VERSION 5.7 ;
BUSBITCHARS "[]" ;
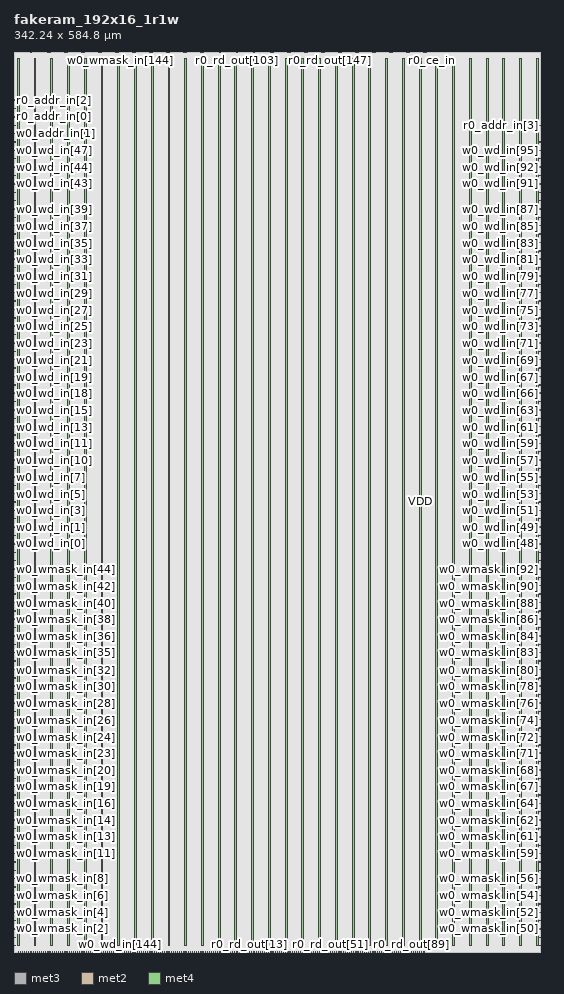
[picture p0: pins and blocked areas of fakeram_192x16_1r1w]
MACRO fakeram_192x16_1r1w
  FOREIGN fakeram_192x16_1r1w 0 0 ;
  SYMMETRY X Y R90 ;
  SIZE 342.240 BY 584.800 ;
  CLASS BLOCK ;
  PIN w0_wmask_in[0]
    DIRECTION INPUT ;
    USE SIGNAL ;
    SHAPE ABUTMENT ;
    PORT
      LAYER met3 ;
      RECT 0.000 3.930 0.900 4.230 ;
    END
  END w0_wmask_in[0]
  PIN w0_wmask_in[1]
    DIRECTION INPUT ;
    USE SIGNAL ;
    SHAPE ABUTMENT ;
    PORT
      LAYER met3 ;
      RECT 0.000 9.370 0.900 9.670 ;
    END
  END w0_wmask_in[1]
  PIN w0_wmask_in[2]
    DIRECTION INPUT ;
    USE SIGNAL ;
    SHAPE ABUTMENT ;
    PORT
      LAYER met3 ;
      RECT 0.000 14.810 0.900 15.110 ;
    END
  END w0_wmask_in[2]
  PIN w0_wmask_in[3]
    DIRECTION INPUT ;
    USE SIGNAL ;
    SHAPE ABUTMENT ;
    PORT
      LAYER met3 ;
      RECT 0.000 20.250 0.900 20.550 ;
    END
  END w0_wmask_in[3]
  PIN w0_wmask_in[4]
    DIRECTION INPUT ;
    USE SIGNAL ;
    SHAPE ABUTMENT ;
    PORT
      LAYER met3 ;
      RECT 0.000 25.690 0.900 25.990 ;
    END
  END w0_wmask_in[4]
  PIN w0_wmask_in[5]
    DIRECTION INPUT ;
    USE SIGNAL ;
    SHAPE ABUTMENT ;
    PORT
      LAYER met3 ;
      RECT 0.000 31.130 0.900 31.430 ;
    END
  END w0_wmask_in[5]
  PIN w0_wmask_in[6]
    DIRECTION INPUT ;
    USE SIGNAL ;
    SHAPE ABUTMENT ;
    PORT
      LAYER met3 ;
      RECT 0.000 36.570 0.900 36.870 ;
    END
  END w0_wmask_in[6]
  PIN w0_wmask_in[7]
    DIRECTION INPUT ;
    USE SIGNAL ;
    SHAPE ABUTMENT ;
    PORT
      LAYER met3 ;
      RECT 0.000 42.010 0.900 42.310 ;
    END
  END w0_wmask_in[7]
  PIN w0_wmask_in[8]
    DIRECTION INPUT ;
    USE SIGNAL ;
    SHAPE ABUTMENT ;
    PORT
      LAYER met3 ;
      RECT 0.000 47.450 0.900 47.750 ;
    END
  END w0_wmask_in[8]
  PIN w0_wmask_in[9]
    DIRECTION INPUT ;
    USE SIGNAL ;
    SHAPE ABUTMENT ;
    PORT
      LAYER met3 ;
      RECT 0.000 52.890 0.900 53.190 ;
    END
  END w0_wmask_in[9]
  PIN w0_wmask_in[10]
    DIRECTION INPUT ;
    USE SIGNAL ;
    SHAPE ABUTMENT ;
    PORT
      LAYER met3 ;
      RECT 0.000 58.330 0.900 58.630 ;
    END
  END w0_wmask_in[10]
  PIN w0_wmask_in[11]
    DIRECTION INPUT ;
    USE SIGNAL ;
    SHAPE ABUTMENT ;
    PORT
      LAYER met3 ;
      RECT 0.000 63.770 0.900 64.070 ;
    END
  END w0_wmask_in[11]
  PIN w0_wmask_in[12]
    DIRECTION INPUT ;
    USE SIGNAL ;
    SHAPE ABUTMENT ;
    PORT
      LAYER met3 ;
      RECT 0.000 69.210 0.900 69.510 ;
    END
  END w0_wmask_in[12]
  PIN w0_wmask_in[13]
    DIRECTION INPUT ;
    USE SIGNAL ;
    SHAPE ABUTMENT ;
    PORT
      LAYER met3 ;
      RECT 0.000 74.650 0.900 74.950 ;
    END
  END w0_wmask_in[13]
  PIN w0_wmask_in[14]
    DIRECTION INPUT ;
    USE SIGNAL ;
    SHAPE ABUTMENT ;
    PORT
      LAYER met3 ;
      RECT 0.000 80.090 0.900 80.390 ;
    END
  END w0_wmask_in[14]
  PIN w0_wmask_in[15]
    DIRECTION INPUT ;
    USE SIGNAL ;
    SHAPE ABUTMENT ;
    PORT
      LAYER met3 ;
      RECT 0.000 85.530 0.900 85.830 ;
    END
  END w0_wmask_in[15]
  PIN w0_wmask_in[16]
    DIRECTION INPUT ;
    USE SIGNAL ;
    SHAPE ABUTMENT ;
    PORT
      LAYER met3 ;
      RECT 0.000 90.970 0.900 91.270 ;
    END
  END w0_wmask_in[16]
  PIN w0_wmask_in[17]
    DIRECTION INPUT ;
    USE SIGNAL ;
    SHAPE ABUTMENT ;
    PORT
      LAYER met3 ;
      RECT 0.000 96.410 0.900 96.710 ;
    END
  END w0_wmask_in[17]
  PIN w0_wmask_in[18]
    DIRECTION INPUT ;
    USE SIGNAL ;
    SHAPE ABUTMENT ;
    PORT
      LAYER met3 ;
      RECT 0.000 101.850 0.900 102.150 ;
    END
  END w0_wmask_in[18]
  PIN w0_wmask_in[19]
    DIRECTION INPUT ;
    USE SIGNAL ;
    SHAPE ABUTMENT ;
    PORT
      LAYER met3 ;
      RECT 0.000 107.290 0.900 107.590 ;
    END
  END w0_wmask_in[19]
  PIN w0_wmask_in[20]
    DIRECTION INPUT ;
    USE SIGNAL ;
    SHAPE ABUTMENT ;
    PORT
      LAYER met3 ;
      RECT 0.000 112.730 0.900 113.030 ;
    END
  END w0_wmask_in[20]
  PIN w0_wmask_in[21]
    DIRECTION INPUT ;
    USE SIGNAL ;
    SHAPE ABUTMENT ;
    PORT
      LAYER met3 ;
      RECT 0.000 118.170 0.900 118.470 ;
    END
  END w0_wmask_in[21]
  PIN w0_wmask_in[22]
    DIRECTION INPUT ;
    USE SIGNAL ;
    SHAPE ABUTMENT ;
    PORT
      LAYER met3 ;
      RECT 0.000 123.610 0.900 123.910 ;
    END
  END w0_wmask_in[22]
  PIN w0_wmask_in[23]
    DIRECTION INPUT ;
    USE SIGNAL ;
    SHAPE ABUTMENT ;
    PORT
      LAYER met3 ;
      RECT 0.000 129.050 0.900 129.350 ;
    END
  END w0_wmask_in[23]
  PIN w0_wmask_in[24]
    DIRECTION INPUT ;
    USE SIGNAL ;
    SHAPE ABUTMENT ;
    PORT
      LAYER met3 ;
      RECT 0.000 134.490 0.900 134.790 ;
    END
  END w0_wmask_in[24]
  PIN w0_wmask_in[25]
    DIRECTION INPUT ;
    USE SIGNAL ;
    SHAPE ABUTMENT ;
    PORT
      LAYER met3 ;
      RECT 0.000 139.930 0.900 140.230 ;
    END
  END w0_wmask_in[25]
  PIN w0_wmask_in[26]
    DIRECTION INPUT ;
    USE SIGNAL ;
    SHAPE ABUTMENT ;
    PORT
      LAYER met3 ;
      RECT 0.000 145.370 0.900 145.670 ;
    END
  END w0_wmask_in[26]
  PIN w0_wmask_in[27]
    DIRECTION INPUT ;
    USE SIGNAL ;
    SHAPE ABUTMENT ;
    PORT
      LAYER met3 ;
      RECT 0.000 150.810 0.900 151.110 ;
    END
  END w0_wmask_in[27]
  PIN w0_wmask_in[28]
    DIRECTION INPUT ;
    USE SIGNAL ;
    SHAPE ABUTMENT ;
    PORT
      LAYER met3 ;
      RECT 0.000 156.250 0.900 156.550 ;
    END
  END w0_wmask_in[28]
  PIN w0_wmask_in[29]
    DIRECTION INPUT ;
    USE SIGNAL ;
    SHAPE ABUTMENT ;
    PORT
      LAYER met3 ;
      RECT 0.000 161.690 0.900 161.990 ;
    END
  END w0_wmask_in[29]
  PIN w0_wmask_in[30]
    DIRECTION INPUT ;
    USE SIGNAL ;
    SHAPE ABUTMENT ;
    PORT
      LAYER met3 ;
      RECT 0.000 167.130 0.900 167.430 ;
    END
  END w0_wmask_in[30]
  PIN w0_wmask_in[31]
    DIRECTION INPUT ;
    USE SIGNAL ;
    SHAPE ABUTMENT ;
    PORT
      LAYER met3 ;
      RECT 0.000 172.570 0.900 172.870 ;
    END
  END w0_wmask_in[31]
  PIN w0_wmask_in[32]
    DIRECTION INPUT ;
    USE SIGNAL ;
    SHAPE ABUTMENT ;
    PORT
      LAYER met3 ;
      RECT 0.000 178.010 0.900 178.310 ;
    END
  END w0_wmask_in[32]
  PIN w0_wmask_in[33]
    DIRECTION INPUT ;
    USE SIGNAL ;
    SHAPE ABUTMENT ;
    PORT
      LAYER met3 ;
      RECT 0.000 183.450 0.900 183.750 ;
    END
  END w0_wmask_in[33]
  PIN w0_wmask_in[34]
    DIRECTION INPUT ;
    USE SIGNAL ;
    SHAPE ABUTMENT ;
    PORT
      LAYER met3 ;
      RECT 0.000 188.890 0.900 189.190 ;
    END
  END w0_wmask_in[34]
  PIN w0_wmask_in[35]
    DIRECTION INPUT ;
    USE SIGNAL ;
    SHAPE ABUTMENT ;
    PORT
      LAYER met3 ;
      RECT 0.000 194.330 0.900 194.630 ;
    END
  END w0_wmask_in[35]
  PIN w0_wmask_in[36]
    DIRECTION INPUT ;
    USE SIGNAL ;
    SHAPE ABUTMENT ;
    PORT
      LAYER met3 ;
      RECT 0.000 199.770 0.900 200.070 ;
    END
  END w0_wmask_in[36]
  PIN w0_wmask_in[37]
    DIRECTION INPUT ;
    USE SIGNAL ;
    SHAPE ABUTMENT ;
    PORT
      LAYER met3 ;
      RECT 0.000 205.210 0.900 205.510 ;
    END
  END w0_wmask_in[37]
  PIN w0_wmask_in[38]
    DIRECTION INPUT ;
    USE SIGNAL ;
    SHAPE ABUTMENT ;
    PORT
      LAYER met3 ;
      RECT 0.000 210.650 0.900 210.950 ;
    END
  END w0_wmask_in[38]
  PIN w0_wmask_in[39]
    DIRECTION INPUT ;
    USE SIGNAL ;
    SHAPE ABUTMENT ;
    PORT
      LAYER met3 ;
      RECT 0.000 216.090 0.900 216.390 ;
    END
  END w0_wmask_in[39]
  PIN w0_wmask_in[40]
    DIRECTION INPUT ;
    USE SIGNAL ;
    SHAPE ABUTMENT ;
    PORT
      LAYER met3 ;
      RECT 0.000 221.530 0.900 221.830 ;
    END
  END w0_wmask_in[40]
  PIN w0_wmask_in[41]
    DIRECTION INPUT ;
    USE SIGNAL ;
    SHAPE ABUTMENT ;
    PORT
      LAYER met3 ;
      RECT 0.000 226.970 0.900 227.270 ;
    END
  END w0_wmask_in[41]
  PIN w0_wmask_in[42]
    DIRECTION INPUT ;
    USE SIGNAL ;
    SHAPE ABUTMENT ;
    PORT
      LAYER met3 ;
      RECT 0.000 232.410 0.900 232.710 ;
    END
  END w0_wmask_in[42]
  PIN w0_wmask_in[43]
    DIRECTION INPUT ;
    USE SIGNAL ;
    SHAPE ABUTMENT ;
    PORT
      LAYER met3 ;
      RECT 0.000 237.850 0.900 238.150 ;
    END
  END w0_wmask_in[43]
  PIN w0_wmask_in[44]
    DIRECTION INPUT ;
    USE SIGNAL ;
    SHAPE ABUTMENT ;
    PORT
      LAYER met3 ;
      RECT 0.000 243.290 0.900 243.590 ;
    END
  END w0_wmask_in[44]
  PIN w0_wmask_in[45]
    DIRECTION INPUT ;
    USE SIGNAL ;
    SHAPE ABUTMENT ;
    PORT
      LAYER met3 ;
      RECT 0.000 248.730 0.900 249.030 ;
    END
  END w0_wmask_in[45]
  PIN w0_wmask_in[46]
    DIRECTION INPUT ;
    USE SIGNAL ;
    SHAPE ABUTMENT ;
    PORT
      LAYER met3 ;
      RECT 0.000 254.170 0.900 254.470 ;
    END
  END w0_wmask_in[46]
  PIN w0_wmask_in[47]
    DIRECTION INPUT ;
    USE SIGNAL ;
    SHAPE ABUTMENT ;
    PORT
      LAYER met3 ;
      RECT 0.000 259.610 0.900 259.910 ;
    END
  END w0_wmask_in[47]
  PIN w0_wmask_in[48]
    DIRECTION INPUT ;
    USE SIGNAL ;
    SHAPE ABUTMENT ;
    PORT
      LAYER met3 ;
      RECT 341.340 3.930 342.240 4.230 ;
    END
  END w0_wmask_in[48]
  PIN w0_wmask_in[49]
    DIRECTION INPUT ;
    USE SIGNAL ;
    SHAPE ABUTMENT ;
    PORT
      LAYER met3 ;
      RECT 341.340 9.370 342.240 9.670 ;
    END
  END w0_wmask_in[49]
  PIN w0_wmask_in[50]
    DIRECTION INPUT ;
    USE SIGNAL ;
    SHAPE ABUTMENT ;
    PORT
      LAYER met3 ;
      RECT 341.340 14.810 342.240 15.110 ;
    END
  END w0_wmask_in[50]
  PIN w0_wmask_in[51]
    DIRECTION INPUT ;
    USE SIGNAL ;
    SHAPE ABUTMENT ;
    PORT
      LAYER met3 ;
      RECT 341.340 20.250 342.240 20.550 ;
    END
  END w0_wmask_in[51]
  PIN w0_wmask_in[52]
    DIRECTION INPUT ;
    USE SIGNAL ;
    SHAPE ABUTMENT ;
    PORT
      LAYER met3 ;
      RECT 341.340 25.690 342.240 25.990 ;
    END
  END w0_wmask_in[52]
  PIN w0_wmask_in[53]
    DIRECTION INPUT ;
    USE SIGNAL ;
    SHAPE ABUTMENT ;
    PORT
      LAYER met3 ;
      RECT 341.340 31.130 342.240 31.430 ;
    END
  END w0_wmask_in[53]
  PIN w0_wmask_in[54]
    DIRECTION INPUT ;
    USE SIGNAL ;
    SHAPE ABUTMENT ;
    PORT
      LAYER met3 ;
      RECT 341.340 36.570 342.240 36.870 ;
    END
  END w0_wmask_in[54]
  PIN w0_wmask_in[55]
    DIRECTION INPUT ;
    USE SIGNAL ;
    SHAPE ABUTMENT ;
    PORT
      LAYER met3 ;
      RECT 341.340 42.010 342.240 42.310 ;
    END
  END w0_wmask_in[55]
  PIN w0_wmask_in[56]
    DIRECTION INPUT ;
    USE SIGNAL ;
    SHAPE ABUTMENT ;
    PORT
      LAYER met3 ;
      RECT 341.340 47.450 342.240 47.750 ;
    END
  END w0_wmask_in[56]
  PIN w0_wmask_in[57]
    DIRECTION INPUT ;
    USE SIGNAL ;
    SHAPE ABUTMENT ;
    PORT
      LAYER met3 ;
      RECT 341.340 52.890 342.240 53.190 ;
    END
  END w0_wmask_in[57]
  PIN w0_wmask_in[58]
    DIRECTION INPUT ;
    USE SIGNAL ;
    SHAPE ABUTMENT ;
    PORT
      LAYER met3 ;
      RECT 341.340 58.330 342.240 58.630 ;
    END
  END w0_wmask_in[58]
  PIN w0_wmask_in[59]
    DIRECTION INPUT ;
    USE SIGNAL ;
    SHAPE ABUTMENT ;
    PORT
      LAYER met3 ;
      RECT 341.340 63.770 342.240 64.070 ;
    END
  END w0_wmask_in[59]
  PIN w0_wmask_in[60]
    DIRECTION INPUT ;
    USE SIGNAL ;
    SHAPE ABUTMENT ;
    PORT
      LAYER met3 ;
      RECT 341.340 69.210 342.240 69.510 ;
    END
  END w0_wmask_in[60]
  PIN w0_wmask_in[61]
    DIRECTION INPUT ;
    USE SIGNAL ;
    SHAPE ABUTMENT ;
    PORT
      LAYER met3 ;
      RECT 341.340 74.650 342.240 74.950 ;
    END
  END w0_wmask_in[61]
  PIN w0_wmask_in[62]
    DIRECTION INPUT ;
    USE SIGNAL ;
    SHAPE ABUTMENT ;
    PORT
      LAYER met3 ;
      RECT 341.340 80.090 342.240 80.390 ;
    END
  END w0_wmask_in[62]
  PIN w0_wmask_in[63]
    DIRECTION INPUT ;
    USE SIGNAL ;
    SHAPE ABUTMENT ;
    PORT
      LAYER met3 ;
      RECT 341.340 85.530 342.240 85.830 ;
    END
  END w0_wmask_in[63]
  PIN w0_wmask_in[64]
    DIRECTION INPUT ;
    USE SIGNAL ;
    SHAPE ABUTMENT ;
    PORT
      LAYER met3 ;
      RECT 341.340 90.970 342.240 91.270 ;
    END
  END w0_wmask_in[64]
  PIN w0_wmask_in[65]
    DIRECTION INPUT ;
    USE SIGNAL ;
    SHAPE ABUTMENT ;
    PORT
      LAYER met3 ;
      RECT 341.340 96.410 342.240 96.710 ;
    END
  END w0_wmask_in[65]
  PIN w0_wmask_in[66]
    DIRECTION INPUT ;
    USE SIGNAL ;
    SHAPE ABUTMENT ;
    PORT
      LAYER met3 ;
      RECT 341.340 101.850 342.240 102.150 ;
    END
  END w0_wmask_in[66]
  PIN w0_wmask_in[67]
    DIRECTION INPUT ;
    USE SIGNAL ;
    SHAPE ABUTMENT ;
    PORT
      LAYER met3 ;
      RECT 341.340 107.290 342.240 107.590 ;
    END
  END w0_wmask_in[67]
  PIN w0_wmask_in[68]
    DIRECTION INPUT ;
    USE SIGNAL ;
    SHAPE ABUTMENT ;
    PORT
      LAYER met3 ;
      RECT 341.340 112.730 342.240 113.030 ;
    END
  END w0_wmask_in[68]
  PIN w0_wmask_in[69]
    DIRECTION INPUT ;
    USE SIGNAL ;
    SHAPE ABUTMENT ;
    PORT
      LAYER met3 ;
      RECT 341.340 118.170 342.240 118.470 ;
    END
  END w0_wmask_in[69]
  PIN w0_wmask_in[70]
    DIRECTION INPUT ;
    USE SIGNAL ;
    SHAPE ABUTMENT ;
    PORT
      LAYER met3 ;
      RECT 341.340 123.610 342.240 123.910 ;
    END
  END w0_wmask_in[70]
  PIN w0_wmask_in[71]
    DIRECTION INPUT ;
    USE SIGNAL ;
    SHAPE ABUTMENT ;
    PORT
      LAYER met3 ;
      RECT 341.340 129.050 342.240 129.350 ;
    END
  END w0_wmask_in[71]
  PIN w0_wmask_in[72]
    DIRECTION INPUT ;
    USE SIGNAL ;
    SHAPE ABUTMENT ;
    PORT
      LAYER met3 ;
      RECT 341.340 134.490 342.240 134.790 ;
    END
  END w0_wmask_in[72]
  PIN w0_wmask_in[73]
    DIRECTION INPUT ;
    USE SIGNAL ;
    SHAPE ABUTMENT ;
    PORT
      LAYER met3 ;
      RECT 341.340 139.930 342.240 140.230 ;
    END
  END w0_wmask_in[73]
  PIN w0_wmask_in[74]
    DIRECTION INPUT ;
    USE SIGNAL ;
    SHAPE ABUTMENT ;
    PORT
      LAYER met3 ;
      RECT 341.340 145.370 342.240 145.670 ;
    END
  END w0_wmask_in[74]
  PIN w0_wmask_in[75]
    DIRECTION INPUT ;
    USE SIGNAL ;
    SHAPE ABUTMENT ;
    PORT
      LAYER met3 ;
      RECT 341.340 150.810 342.240 151.110 ;
    END
  END w0_wmask_in[75]
  PIN w0_wmask_in[76]
    DIRECTION INPUT ;
    USE SIGNAL ;
    SHAPE ABUTMENT ;
    PORT
      LAYER met3 ;
      RECT 341.340 156.250 342.240 156.550 ;
    END
  END w0_wmask_in[76]
  PIN w0_wmask_in[77]
    DIRECTION INPUT ;
    USE SIGNAL ;
    SHAPE ABUTMENT ;
    PORT
      LAYER met3 ;
      RECT 341.340 161.690 342.240 161.990 ;
    END
  END w0_wmask_in[77]
  PIN w0_wmask_in[78]
    DIRECTION INPUT ;
    USE SIGNAL ;
    SHAPE ABUTMENT ;
    PORT
      LAYER met3 ;
      RECT 341.340 167.130 342.240 167.430 ;
    END
  END w0_wmask_in[78]
  PIN w0_wmask_in[79]
    DIRECTION INPUT ;
    USE SIGNAL ;
    SHAPE ABUTMENT ;
    PORT
      LAYER met3 ;
      RECT 341.340 172.570 342.240 172.870 ;
    END
  END w0_wmask_in[79]
  PIN w0_wmask_in[80]
    DIRECTION INPUT ;
    USE SIGNAL ;
    SHAPE ABUTMENT ;
    PORT
      LAYER met3 ;
      RECT 341.340 178.010 342.240 178.310 ;
    END
  END w0_wmask_in[80]
  PIN w0_wmask_in[81]
    DIRECTION INPUT ;
    USE SIGNAL ;
    SHAPE ABUTMENT ;
    PORT
      LAYER met3 ;
      RECT 341.340 183.450 342.240 183.750 ;
    END
  END w0_wmask_in[81]
  PIN w0_wmask_in[82]
    DIRECTION INPUT ;
    USE SIGNAL ;
    SHAPE ABUTMENT ;
    PORT
      LAYER met3 ;
      RECT 341.340 188.890 342.240 189.190 ;
    END
  END w0_wmask_in[82]
  PIN w0_wmask_in[83]
    DIRECTION INPUT ;
    USE SIGNAL ;
    SHAPE ABUTMENT ;
    PORT
      LAYER met3 ;
      RECT 341.340 194.330 342.240 194.630 ;
    END
  END w0_wmask_in[83]
  PIN w0_wmask_in[84]
    DIRECTION INPUT ;
    USE SIGNAL ;
    SHAPE ABUTMENT ;
    PORT
      LAYER met3 ;
      RECT 341.340 199.770 342.240 200.070 ;
    END
  END w0_wmask_in[84]
  PIN w0_wmask_in[85]
    DIRECTION INPUT ;
    USE SIGNAL ;
    SHAPE ABUTMENT ;
    PORT
      LAYER met3 ;
      RECT 341.340 205.210 342.240 205.510 ;
    END
  END w0_wmask_in[85]
  PIN w0_wmask_in[86]
    DIRECTION INPUT ;
    USE SIGNAL ;
    SHAPE ABUTMENT ;
    PORT
      LAYER met3 ;
      RECT 341.340 210.650 342.240 210.950 ;
    END
  END w0_wmask_in[86]
  PIN w0_wmask_in[87]
    DIRECTION INPUT ;
    USE SIGNAL ;
    SHAPE ABUTMENT ;
    PORT
      LAYER met3 ;
      RECT 341.340 216.090 342.240 216.390 ;
    END
  END w0_wmask_in[87]
  PIN w0_wmask_in[88]
    DIRECTION INPUT ;
    USE SIGNAL ;
    SHAPE ABUTMENT ;
    PORT
      LAYER met3 ;
      RECT 341.340 221.530 342.240 221.830 ;
    END
  END w0_wmask_in[88]
  PIN w0_wmask_in[89]
    DIRECTION INPUT ;
    USE SIGNAL ;
    SHAPE ABUTMENT ;
    PORT
      LAYER met3 ;
      RECT 341.340 226.970 342.240 227.270 ;
    END
  END w0_wmask_in[89]
  PIN w0_wmask_in[90]
    DIRECTION INPUT ;
    USE SIGNAL ;
    SHAPE ABUTMENT ;
    PORT
      LAYER met3 ;
      RECT 341.340 232.410 342.240 232.710 ;
    END
  END w0_wmask_in[90]
  PIN w0_wmask_in[91]
    DIRECTION INPUT ;
    USE SIGNAL ;
    SHAPE ABUTMENT ;
    PORT
      LAYER met3 ;
      RECT 341.340 237.850 342.240 238.150 ;
    END
  END w0_wmask_in[91]
  PIN w0_wmask_in[92]
    DIRECTION INPUT ;
    USE SIGNAL ;
    SHAPE ABUTMENT ;
    PORT
      LAYER met3 ;
      RECT 341.340 243.290 342.240 243.590 ;
    END
  END w0_wmask_in[92]
  PIN w0_wmask_in[93]
    DIRECTION INPUT ;
    USE SIGNAL ;
    SHAPE ABUTMENT ;
    PORT
      LAYER met3 ;
      RECT 341.340 248.730 342.240 249.030 ;
    END
  END w0_wmask_in[93]
  PIN w0_wmask_in[94]
    DIRECTION INPUT ;
    USE SIGNAL ;
    SHAPE ABUTMENT ;
    PORT
      LAYER met3 ;
      RECT 341.340 254.170 342.240 254.470 ;
    END
  END w0_wmask_in[94]
  PIN w0_wmask_in[95]
    DIRECTION INPUT ;
    USE SIGNAL ;
    SHAPE ABUTMENT ;
    PORT
      LAYER met3 ;
      RECT 341.340 259.610 342.240 259.910 ;
    END
  END w0_wmask_in[95]
  PIN w0_wmask_in[96]
    DIRECTION INPUT ;
    USE SIGNAL ;
    SHAPE ABUTMENT ;
    PORT
      LAYER met2 ;
      RECT 2.690 584.380 2.830 584.800 ;
    END
  END w0_wmask_in[96]
  PIN w0_wmask_in[97]
    DIRECTION INPUT ;
    USE SIGNAL ;
    SHAPE ABUTMENT ;
    PORT
      LAYER met2 ;
      RECT 4.070 584.380 4.210 584.800 ;
    END
  END w0_wmask_in[97]
  PIN w0_wmask_in[98]
    DIRECTION INPUT ;
    USE SIGNAL ;
    SHAPE ABUTMENT ;
    PORT
      LAYER met2 ;
      RECT 5.450 584.380 5.590 584.800 ;
    END
  END w0_wmask_in[98]
  PIN w0_wmask_in[99]
    DIRECTION INPUT ;
    USE SIGNAL ;
    SHAPE ABUTMENT ;
    PORT
      LAYER met2 ;
      RECT 6.830 584.380 6.970 584.800 ;
    END
  END w0_wmask_in[99]
  PIN w0_wmask_in[100]
    DIRECTION INPUT ;
    USE SIGNAL ;
    SHAPE ABUTMENT ;
    PORT
      LAYER met2 ;
      RECT 8.210 584.380 8.350 584.800 ;
    END
  END w0_wmask_in[100]
  PIN w0_wmask_in[101]
    DIRECTION INPUT ;
    USE SIGNAL ;
    SHAPE ABUTMENT ;
    PORT
      LAYER met2 ;
      RECT 9.590 584.380 9.730 584.800 ;
    END
  END w0_wmask_in[101]
  PIN w0_wmask_in[102]
    DIRECTION INPUT ;
    USE SIGNAL ;
    SHAPE ABUTMENT ;
    PORT
      LAYER met2 ;
      RECT 10.970 584.380 11.110 584.800 ;
    END
  END w0_wmask_in[102]
  PIN w0_wmask_in[103]
    DIRECTION INPUT ;
    USE SIGNAL ;
    SHAPE ABUTMENT ;
    PORT
      LAYER met2 ;
      RECT 12.350 584.380 12.490 584.800 ;
    END
  END w0_wmask_in[103]
  PIN w0_wmask_in[104]
    DIRECTION INPUT ;
    USE SIGNAL ;
    SHAPE ABUTMENT ;
    PORT
      LAYER met2 ;
      RECT 13.730 584.380 13.870 584.800 ;
    END
  END w0_wmask_in[104]
  PIN w0_wmask_in[105]
    DIRECTION INPUT ;
    USE SIGNAL ;
    SHAPE ABUTMENT ;
    PORT
      LAYER met2 ;
      RECT 15.110 584.380 15.250 584.800 ;
    END
  END w0_wmask_in[105]
  PIN w0_wmask_in[106]
    DIRECTION INPUT ;
    USE SIGNAL ;
    SHAPE ABUTMENT ;
    PORT
      LAYER met2 ;
      RECT 16.490 584.380 16.630 584.800 ;
    END
  END w0_wmask_in[106]
  PIN w0_wmask_in[107]
    DIRECTION INPUT ;
    USE SIGNAL ;
    SHAPE ABUTMENT ;
    PORT
      LAYER met2 ;
      RECT 17.870 584.380 18.010 584.800 ;
    END
  END w0_wmask_in[107]
  PIN w0_wmask_in[108]
    DIRECTION INPUT ;
    USE SIGNAL ;
    SHAPE ABUTMENT ;
    PORT
      LAYER met2 ;
      RECT 19.250 584.380 19.390 584.800 ;
    END
  END w0_wmask_in[108]
  PIN w0_wmask_in[109]
    DIRECTION INPUT ;
    USE SIGNAL ;
    SHAPE ABUTMENT ;
    PORT
      LAYER met2 ;
      RECT 20.630 584.380 20.770 584.800 ;
    END
  END w0_wmask_in[109]
  PIN w0_wmask_in[110]
    DIRECTION INPUT ;
    USE SIGNAL ;
    SHAPE ABUTMENT ;
    PORT
      LAYER met2 ;
      RECT 22.010 584.380 22.150 584.800 ;
    END
  END w0_wmask_in[110]
  PIN w0_wmask_in[111]
    DIRECTION INPUT ;
    USE SIGNAL ;
    SHAPE ABUTMENT ;
    PORT
      LAYER met2 ;
      RECT 23.390 584.380 23.530 584.800 ;
    END
  END w0_wmask_in[111]
  PIN w0_wmask_in[112]
    DIRECTION INPUT ;
    USE SIGNAL ;
    SHAPE ABUTMENT ;
    PORT
      LAYER met2 ;
      RECT 24.770 584.380 24.910 584.800 ;
    END
  END w0_wmask_in[112]
  PIN w0_wmask_in[113]
    DIRECTION INPUT ;
    USE SIGNAL ;
    SHAPE ABUTMENT ;
    PORT
      LAYER met2 ;
      RECT 26.150 584.380 26.290 584.800 ;
    END
  END w0_wmask_in[113]
  PIN w0_wmask_in[114]
    DIRECTION INPUT ;
    USE SIGNAL ;
    SHAPE ABUTMENT ;
    PORT
      LAYER met2 ;
      RECT 27.530 584.380 27.670 584.800 ;
    END
  END w0_wmask_in[114]
  PIN w0_wmask_in[115]
    DIRECTION INPUT ;
    USE SIGNAL ;
    SHAPE ABUTMENT ;
    PORT
      LAYER met2 ;
      RECT 28.910 584.380 29.050 584.800 ;
    END
  END w0_wmask_in[115]
  PIN w0_wmask_in[116]
    DIRECTION INPUT ;
    USE SIGNAL ;
    SHAPE ABUTMENT ;
    PORT
      LAYER met2 ;
      RECT 30.290 584.380 30.430 584.800 ;
    END
  END w0_wmask_in[116]
  PIN w0_wmask_in[117]
    DIRECTION INPUT ;
    USE SIGNAL ;
    SHAPE ABUTMENT ;
    PORT
      LAYER met2 ;
      RECT 31.670 584.380 31.810 584.800 ;
    END
  END w0_wmask_in[117]
  PIN w0_wmask_in[118]
    DIRECTION INPUT ;
    USE SIGNAL ;
    SHAPE ABUTMENT ;
    PORT
      LAYER met2 ;
      RECT 33.050 584.380 33.190 584.800 ;
    END
  END w0_wmask_in[118]
  PIN w0_wmask_in[119]
    DIRECTION INPUT ;
    USE SIGNAL ;
    SHAPE ABUTMENT ;
    PORT
      LAYER met2 ;
      RECT 34.430 584.380 34.570 584.800 ;
    END
  END w0_wmask_in[119]
  PIN w0_wmask_in[120]
    DIRECTION INPUT ;
    USE SIGNAL ;
    SHAPE ABUTMENT ;
    PORT
      LAYER met2 ;
      RECT 35.810 584.380 35.950 584.800 ;
    END
  END w0_wmask_in[120]
  PIN w0_wmask_in[121]
    DIRECTION INPUT ;
    USE SIGNAL ;
    SHAPE ABUTMENT ;
    PORT
      LAYER met2 ;
      RECT 37.190 584.380 37.330 584.800 ;
    END
  END w0_wmask_in[121]
  PIN w0_wmask_in[122]
    DIRECTION INPUT ;
    USE SIGNAL ;
    SHAPE ABUTMENT ;
    PORT
      LAYER met2 ;
      RECT 38.570 584.380 38.710 584.800 ;
    END
  END w0_wmask_in[122]
  PIN w0_wmask_in[123]
    DIRECTION INPUT ;
    USE SIGNAL ;
    SHAPE ABUTMENT ;
    PORT
      LAYER met2 ;
      RECT 39.950 584.380 40.090 584.800 ;
    END
  END w0_wmask_in[123]
  PIN w0_wmask_in[124]
    DIRECTION INPUT ;
    USE SIGNAL ;
    SHAPE ABUTMENT ;
    PORT
      LAYER met2 ;
      RECT 41.330 584.380 41.470 584.800 ;
    END
  END w0_wmask_in[124]
  PIN w0_wmask_in[125]
    DIRECTION INPUT ;
    USE SIGNAL ;
    SHAPE ABUTMENT ;
    PORT
      LAYER met2 ;
      RECT 42.710 584.380 42.850 584.800 ;
    END
  END w0_wmask_in[125]
  PIN w0_wmask_in[126]
    DIRECTION INPUT ;
    USE SIGNAL ;
    SHAPE ABUTMENT ;
    PORT
      LAYER met2 ;
      RECT 44.090 584.380 44.230 584.800 ;
    END
  END w0_wmask_in[126]
  PIN w0_wmask_in[127]
    DIRECTION INPUT ;
    USE SIGNAL ;
    SHAPE ABUTMENT ;
    PORT
      LAYER met2 ;
      RECT 45.470 584.380 45.610 584.800 ;
    END
  END w0_wmask_in[127]
  PIN w0_wmask_in[128]
    DIRECTION INPUT ;
    USE SIGNAL ;
    SHAPE ABUTMENT ;
    PORT
      LAYER met2 ;
      RECT 46.850 584.380 46.990 584.800 ;
    END
  END w0_wmask_in[128]
  PIN w0_wmask_in[129]
    DIRECTION INPUT ;
    USE SIGNAL ;
    SHAPE ABUTMENT ;
    PORT
      LAYER met2 ;
      RECT 48.230 584.380 48.370 584.800 ;
    END
  END w0_wmask_in[129]
  PIN w0_wmask_in[130]
    DIRECTION INPUT ;
    USE SIGNAL ;
    SHAPE ABUTMENT ;
    PORT
      LAYER met2 ;
      RECT 49.610 584.380 49.750 584.800 ;
    END
  END w0_wmask_in[130]
  PIN w0_wmask_in[131]
    DIRECTION INPUT ;
    USE SIGNAL ;
    SHAPE ABUTMENT ;
    PORT
      LAYER met2 ;
      RECT 50.990 584.380 51.130 584.800 ;
    END
  END w0_wmask_in[131]
  PIN w0_wmask_in[132]
    DIRECTION INPUT ;
    USE SIGNAL ;
    SHAPE ABUTMENT ;
    PORT
      LAYER met2 ;
      RECT 52.370 584.380 52.510 584.800 ;
    END
  END w0_wmask_in[132]
  PIN w0_wmask_in[133]
    DIRECTION INPUT ;
    USE SIGNAL ;
    SHAPE ABUTMENT ;
    PORT
      LAYER met2 ;
      RECT 53.750 584.380 53.890 584.800 ;
    END
  END w0_wmask_in[133]
  PIN w0_wmask_in[134]
    DIRECTION INPUT ;
    USE SIGNAL ;
    SHAPE ABUTMENT ;
    PORT
      LAYER met2 ;
      RECT 55.130 584.380 55.270 584.800 ;
    END
  END w0_wmask_in[134]
  PIN w0_wmask_in[135]
    DIRECTION INPUT ;
    USE SIGNAL ;
    SHAPE ABUTMENT ;
    PORT
      LAYER met2 ;
      RECT 56.510 584.380 56.650 584.800 ;
    END
  END w0_wmask_in[135]
  PIN w0_wmask_in[136]
    DIRECTION INPUT ;
    USE SIGNAL ;
    SHAPE ABUTMENT ;
    PORT
      LAYER met2 ;
      RECT 57.890 584.380 58.030 584.800 ;
    END
  END w0_wmask_in[136]
  PIN w0_wmask_in[137]
    DIRECTION INPUT ;
    USE SIGNAL ;
    SHAPE ABUTMENT ;
    PORT
      LAYER met2 ;
      RECT 59.270 584.380 59.410 584.800 ;
    END
  END w0_wmask_in[137]
  PIN w0_wmask_in[138]
    DIRECTION INPUT ;
    USE SIGNAL ;
    SHAPE ABUTMENT ;
    PORT
      LAYER met2 ;
      RECT 60.650 584.380 60.790 584.800 ;
    END
  END w0_wmask_in[138]
  PIN w0_wmask_in[139]
    DIRECTION INPUT ;
    USE SIGNAL ;
    SHAPE ABUTMENT ;
    PORT
      LAYER met2 ;
      RECT 62.030 584.380 62.170 584.800 ;
    END
  END w0_wmask_in[139]
  PIN w0_wmask_in[140]
    DIRECTION INPUT ;
    USE SIGNAL ;
    SHAPE ABUTMENT ;
    PORT
      LAYER met2 ;
      RECT 63.410 584.380 63.550 584.800 ;
    END
  END w0_wmask_in[140]
  PIN w0_wmask_in[141]
    DIRECTION INPUT ;
    USE SIGNAL ;
    SHAPE ABUTMENT ;
    PORT
      LAYER met2 ;
      RECT 64.790 584.380 64.930 584.800 ;
    END
  END w0_wmask_in[141]
  PIN w0_wmask_in[142]
    DIRECTION INPUT ;
    USE SIGNAL ;
    SHAPE ABUTMENT ;
    PORT
      LAYER met2 ;
      RECT 66.170 584.380 66.310 584.800 ;
    END
  END w0_wmask_in[142]
  PIN w0_wmask_in[143]
    DIRECTION INPUT ;
    USE SIGNAL ;
    SHAPE ABUTMENT ;
    PORT
      LAYER met2 ;
      RECT 67.550 584.380 67.690 584.800 ;
    END
  END w0_wmask_in[143]
  PIN w0_wmask_in[144]
    DIRECTION INPUT ;
    USE SIGNAL ;
    SHAPE ABUTMENT ;
    PORT
      LAYER met2 ;
      RECT 68.930 584.380 69.070 584.800 ;
    END
  END w0_wmask_in[144]
  PIN w0_wmask_in[145]
    DIRECTION INPUT ;
    USE SIGNAL ;
    SHAPE ABUTMENT ;
    PORT
      LAYER met2 ;
      RECT 70.310 584.380 70.450 584.800 ;
    END
  END w0_wmask_in[145]
  PIN w0_wmask_in[146]
    DIRECTION INPUT ;
    USE SIGNAL ;
    SHAPE ABUTMENT ;
    PORT
      LAYER met2 ;
      RECT 71.690 584.380 71.830 584.800 ;
    END
  END w0_wmask_in[146]
  PIN w0_wmask_in[147]
    DIRECTION INPUT ;
    USE SIGNAL ;
    SHAPE ABUTMENT ;
    PORT
      LAYER met2 ;
      RECT 73.070 584.380 73.210 584.800 ;
    END
  END w0_wmask_in[147]
  PIN w0_wmask_in[148]
    DIRECTION INPUT ;
    USE SIGNAL ;
    SHAPE ABUTMENT ;
    PORT
      LAYER met2 ;
      RECT 74.450 584.380 74.590 584.800 ;
    END
  END w0_wmask_in[148]
  PIN w0_wmask_in[149]
    DIRECTION INPUT ;
    USE SIGNAL ;
    SHAPE ABUTMENT ;
    PORT
      LAYER met2 ;
      RECT 75.830 584.380 75.970 584.800 ;
    END
  END w0_wmask_in[149]
  PIN w0_wmask_in[150]
    DIRECTION INPUT ;
    USE SIGNAL ;
    SHAPE ABUTMENT ;
    PORT
      LAYER met2 ;
      RECT 77.210 584.380 77.350 584.800 ;
    END
  END w0_wmask_in[150]
  PIN w0_wmask_in[151]
    DIRECTION INPUT ;
    USE SIGNAL ;
    SHAPE ABUTMENT ;
    PORT
      LAYER met2 ;
      RECT 78.590 584.380 78.730 584.800 ;
    END
  END w0_wmask_in[151]
  PIN w0_wmask_in[152]
    DIRECTION INPUT ;
    USE SIGNAL ;
    SHAPE ABUTMENT ;
    PORT
      LAYER met2 ;
      RECT 79.970 584.380 80.110 584.800 ;
    END
  END w0_wmask_in[152]
  PIN w0_wmask_in[153]
    DIRECTION INPUT ;
    USE SIGNAL ;
    SHAPE ABUTMENT ;
    PORT
      LAYER met2 ;
      RECT 81.350 584.380 81.490 584.800 ;
    END
  END w0_wmask_in[153]
  PIN w0_wmask_in[154]
    DIRECTION INPUT ;
    USE SIGNAL ;
    SHAPE ABUTMENT ;
    PORT
      LAYER met2 ;
      RECT 82.730 584.380 82.870 584.800 ;
    END
  END w0_wmask_in[154]
  PIN w0_wmask_in[155]
    DIRECTION INPUT ;
    USE SIGNAL ;
    SHAPE ABUTMENT ;
    PORT
      LAYER met2 ;
      RECT 84.110 584.380 84.250 584.800 ;
    END
  END w0_wmask_in[155]
  PIN w0_wmask_in[156]
    DIRECTION INPUT ;
    USE SIGNAL ;
    SHAPE ABUTMENT ;
    PORT
      LAYER met2 ;
      RECT 85.490 584.380 85.630 584.800 ;
    END
  END w0_wmask_in[156]
  PIN w0_wmask_in[157]
    DIRECTION INPUT ;
    USE SIGNAL ;
    SHAPE ABUTMENT ;
    PORT
      LAYER met2 ;
      RECT 86.870 584.380 87.010 584.800 ;
    END
  END w0_wmask_in[157]
  PIN w0_wmask_in[158]
    DIRECTION INPUT ;
    USE SIGNAL ;
    SHAPE ABUTMENT ;
    PORT
      LAYER met2 ;
      RECT 88.250 584.380 88.390 584.800 ;
    END
  END w0_wmask_in[158]
  PIN w0_wmask_in[159]
    DIRECTION INPUT ;
    USE SIGNAL ;
    SHAPE ABUTMENT ;
    PORT
      LAYER met2 ;
      RECT 89.630 584.380 89.770 584.800 ;
    END
  END w0_wmask_in[159]
  PIN w0_wmask_in[160]
    DIRECTION INPUT ;
    USE SIGNAL ;
    SHAPE ABUTMENT ;
    PORT
      LAYER met2 ;
      RECT 91.010 584.380 91.150 584.800 ;
    END
  END w0_wmask_in[160]
  PIN w0_wmask_in[161]
    DIRECTION INPUT ;
    USE SIGNAL ;
    SHAPE ABUTMENT ;
    PORT
      LAYER met2 ;
      RECT 92.390 584.380 92.530 584.800 ;
    END
  END w0_wmask_in[161]
  PIN w0_wmask_in[162]
    DIRECTION INPUT ;
    USE SIGNAL ;
    SHAPE ABUTMENT ;
    PORT
      LAYER met2 ;
      RECT 93.770 584.380 93.910 584.800 ;
    END
  END w0_wmask_in[162]
  PIN w0_wmask_in[163]
    DIRECTION INPUT ;
    USE SIGNAL ;
    SHAPE ABUTMENT ;
    PORT
      LAYER met2 ;
      RECT 95.150 584.380 95.290 584.800 ;
    END
  END w0_wmask_in[163]
  PIN w0_wmask_in[164]
    DIRECTION INPUT ;
    USE SIGNAL ;
    SHAPE ABUTMENT ;
    PORT
      LAYER met2 ;
      RECT 96.530 584.380 96.670 584.800 ;
    END
  END w0_wmask_in[164]
  PIN w0_wmask_in[165]
    DIRECTION INPUT ;
    USE SIGNAL ;
    SHAPE ABUTMENT ;
    PORT
      LAYER met2 ;
      RECT 97.910 584.380 98.050 584.800 ;
    END
  END w0_wmask_in[165]
  PIN w0_wmask_in[166]
    DIRECTION INPUT ;
    USE SIGNAL ;
    SHAPE ABUTMENT ;
    PORT
      LAYER met2 ;
      RECT 99.290 584.380 99.430 584.800 ;
    END
  END w0_wmask_in[166]
  PIN w0_wmask_in[167]
    DIRECTION INPUT ;
    USE SIGNAL ;
    SHAPE ABUTMENT ;
    PORT
      LAYER met2 ;
      RECT 100.670 584.380 100.810 584.800 ;
    END
  END w0_wmask_in[167]
  PIN w0_wmask_in[168]
    DIRECTION INPUT ;
    USE SIGNAL ;
    SHAPE ABUTMENT ;
    PORT
      LAYER met2 ;
      RECT 102.050 584.380 102.190 584.800 ;
    END
  END w0_wmask_in[168]
  PIN w0_wmask_in[169]
    DIRECTION INPUT ;
    USE SIGNAL ;
    SHAPE ABUTMENT ;
    PORT
      LAYER met2 ;
      RECT 103.430 584.380 103.570 584.800 ;
    END
  END w0_wmask_in[169]
  PIN w0_wmask_in[170]
    DIRECTION INPUT ;
    USE SIGNAL ;
    SHAPE ABUTMENT ;
    PORT
      LAYER met2 ;
      RECT 104.810 584.380 104.950 584.800 ;
    END
  END w0_wmask_in[170]
  PIN w0_wmask_in[171]
    DIRECTION INPUT ;
    USE SIGNAL ;
    SHAPE ABUTMENT ;
    PORT
      LAYER met2 ;
      RECT 106.190 584.380 106.330 584.800 ;
    END
  END w0_wmask_in[171]
  PIN w0_wmask_in[172]
    DIRECTION INPUT ;
    USE SIGNAL ;
    SHAPE ABUTMENT ;
    PORT
      LAYER met2 ;
      RECT 107.570 584.380 107.710 584.800 ;
    END
  END w0_wmask_in[172]
  PIN w0_wmask_in[173]
    DIRECTION INPUT ;
    USE SIGNAL ;
    SHAPE ABUTMENT ;
    PORT
      LAYER met2 ;
      RECT 108.950 584.380 109.090 584.800 ;
    END
  END w0_wmask_in[173]
  PIN w0_wmask_in[174]
    DIRECTION INPUT ;
    USE SIGNAL ;
    SHAPE ABUTMENT ;
    PORT
      LAYER met2 ;
      RECT 110.330 584.380 110.470 584.800 ;
    END
  END w0_wmask_in[174]
  PIN w0_wmask_in[175]
    DIRECTION INPUT ;
    USE SIGNAL ;
    SHAPE ABUTMENT ;
    PORT
      LAYER met2 ;
      RECT 111.710 584.380 111.850 584.800 ;
    END
  END w0_wmask_in[175]
  PIN w0_wmask_in[176]
    DIRECTION INPUT ;
    USE SIGNAL ;
    SHAPE ABUTMENT ;
    PORT
      LAYER met2 ;
      RECT 113.090 584.380 113.230 584.800 ;
    END
  END w0_wmask_in[176]
  PIN w0_wmask_in[177]
    DIRECTION INPUT ;
    USE SIGNAL ;
    SHAPE ABUTMENT ;
    PORT
      LAYER met2 ;
      RECT 114.470 584.380 114.610 584.800 ;
    END
  END w0_wmask_in[177]
  PIN w0_wmask_in[178]
    DIRECTION INPUT ;
    USE SIGNAL ;
    SHAPE ABUTMENT ;
    PORT
      LAYER met2 ;
      RECT 115.850 584.380 115.990 584.800 ;
    END
  END w0_wmask_in[178]
  PIN w0_wmask_in[179]
    DIRECTION INPUT ;
    USE SIGNAL ;
    SHAPE ABUTMENT ;
    PORT
      LAYER met2 ;
      RECT 117.230 584.380 117.370 584.800 ;
    END
  END w0_wmask_in[179]
  PIN w0_wmask_in[180]
    DIRECTION INPUT ;
    USE SIGNAL ;
    SHAPE ABUTMENT ;
    PORT
      LAYER met2 ;
      RECT 118.610 584.380 118.750 584.800 ;
    END
  END w0_wmask_in[180]
  PIN w0_wmask_in[181]
    DIRECTION INPUT ;
    USE SIGNAL ;
    SHAPE ABUTMENT ;
    PORT
      LAYER met2 ;
      RECT 119.990 584.380 120.130 584.800 ;
    END
  END w0_wmask_in[181]
  PIN w0_wmask_in[182]
    DIRECTION INPUT ;
    USE SIGNAL ;
    SHAPE ABUTMENT ;
    PORT
      LAYER met2 ;
      RECT 121.370 584.380 121.510 584.800 ;
    END
  END w0_wmask_in[182]
  PIN w0_wmask_in[183]
    DIRECTION INPUT ;
    USE SIGNAL ;
    SHAPE ABUTMENT ;
    PORT
      LAYER met2 ;
      RECT 122.750 584.380 122.890 584.800 ;
    END
  END w0_wmask_in[183]
  PIN w0_wmask_in[184]
    DIRECTION INPUT ;
    USE SIGNAL ;
    SHAPE ABUTMENT ;
    PORT
      LAYER met2 ;
      RECT 124.130 584.380 124.270 584.800 ;
    END
  END w0_wmask_in[184]
  PIN w0_wmask_in[185]
    DIRECTION INPUT ;
    USE SIGNAL ;
    SHAPE ABUTMENT ;
    PORT
      LAYER met2 ;
      RECT 125.510 584.380 125.650 584.800 ;
    END
  END w0_wmask_in[185]
  PIN w0_wmask_in[186]
    DIRECTION INPUT ;
    USE SIGNAL ;
    SHAPE ABUTMENT ;
    PORT
      LAYER met2 ;
      RECT 126.890 584.380 127.030 584.800 ;
    END
  END w0_wmask_in[186]
  PIN w0_wmask_in[187]
    DIRECTION INPUT ;
    USE SIGNAL ;
    SHAPE ABUTMENT ;
    PORT
      LAYER met2 ;
      RECT 128.270 584.380 128.410 584.800 ;
    END
  END w0_wmask_in[187]
  PIN w0_wmask_in[188]
    DIRECTION INPUT ;
    USE SIGNAL ;
    SHAPE ABUTMENT ;
    PORT
      LAYER met2 ;
      RECT 129.650 584.380 129.790 584.800 ;
    END
  END w0_wmask_in[188]
  PIN w0_wmask_in[189]
    DIRECTION INPUT ;
    USE SIGNAL ;
    SHAPE ABUTMENT ;
    PORT
      LAYER met2 ;
      RECT 131.030 584.380 131.170 584.800 ;
    END
  END w0_wmask_in[189]
  PIN w0_wmask_in[190]
    DIRECTION INPUT ;
    USE SIGNAL ;
    SHAPE ABUTMENT ;
    PORT
      LAYER met2 ;
      RECT 132.410 584.380 132.550 584.800 ;
    END
  END w0_wmask_in[190]
  PIN w0_wmask_in[191]
    DIRECTION INPUT ;
    USE SIGNAL ;
    SHAPE ABUTMENT ;
    PORT
      LAYER met2 ;
      RECT 133.790 584.380 133.930 584.800 ;
    END
  END w0_wmask_in[191]
  PIN w0_wd_in[0]
    DIRECTION INPUT ;
    USE SIGNAL ;
    SHAPE ABUTMENT ;
    PORT
      LAYER met3 ;
      RECT 0.000 265.050 0.900 265.350 ;
    END
  END w0_wd_in[0]
  PIN w0_wd_in[1]
    DIRECTION INPUT ;
    USE SIGNAL ;
    SHAPE ABUTMENT ;
    PORT
      LAYER met3 ;
      RECT 0.000 270.490 0.900 270.790 ;
    END
  END w0_wd_in[1]
  PIN w0_wd_in[2]
    DIRECTION INPUT ;
    USE SIGNAL ;
    SHAPE ABUTMENT ;
    PORT
      LAYER met3 ;
      RECT 0.000 275.930 0.900 276.230 ;
    END
  END w0_wd_in[2]
  PIN w0_wd_in[3]
    DIRECTION INPUT ;
    USE SIGNAL ;
    SHAPE ABUTMENT ;
    PORT
      LAYER met3 ;
      RECT 0.000 281.370 0.900 281.670 ;
    END
  END w0_wd_in[3]
  PIN w0_wd_in[4]
    DIRECTION INPUT ;
    USE SIGNAL ;
    SHAPE ABUTMENT ;
    PORT
      LAYER met3 ;
      RECT 0.000 286.810 0.900 287.110 ;
    END
  END w0_wd_in[4]
  PIN w0_wd_in[5]
    DIRECTION INPUT ;
    USE SIGNAL ;
    SHAPE ABUTMENT ;
    PORT
      LAYER met3 ;
      RECT 0.000 292.250 0.900 292.550 ;
    END
  END w0_wd_in[5]
  PIN w0_wd_in[6]
    DIRECTION INPUT ;
    USE SIGNAL ;
    SHAPE ABUTMENT ;
    PORT
      LAYER met3 ;
      RECT 0.000 297.690 0.900 297.990 ;
    END
  END w0_wd_in[6]
  PIN w0_wd_in[7]
    DIRECTION INPUT ;
    USE SIGNAL ;
    SHAPE ABUTMENT ;
    PORT
      LAYER met3 ;
      RECT 0.000 303.130 0.900 303.430 ;
    END
  END w0_wd_in[7]
  PIN w0_wd_in[8]
    DIRECTION INPUT ;
    USE SIGNAL ;
    SHAPE ABUTMENT ;
    PORT
      LAYER met3 ;
      RECT 0.000 308.570 0.900 308.870 ;
    END
  END w0_wd_in[8]
  PIN w0_wd_in[9]
    DIRECTION INPUT ;
    USE SIGNAL ;
    SHAPE ABUTMENT ;
    PORT
      LAYER met3 ;
      RECT 0.000 314.010 0.900 314.310 ;
    END
  END w0_wd_in[9]
  PIN w0_wd_in[10]
    DIRECTION INPUT ;
    USE SIGNAL ;
    SHAPE ABUTMENT ;
    PORT
      LAYER met3 ;
      RECT 0.000 319.450 0.900 319.750 ;
    END
  END w0_wd_in[10]
  PIN w0_wd_in[11]
    DIRECTION INPUT ;
    USE SIGNAL ;
    SHAPE ABUTMENT ;
    PORT
      LAYER met3 ;
      RECT 0.000 324.890 0.900 325.190 ;
    END
  END w0_wd_in[11]
  PIN w0_wd_in[12]
    DIRECTION INPUT ;
    USE SIGNAL ;
    SHAPE ABUTMENT ;
    PORT
      LAYER met3 ;
      RECT 0.000 330.330 0.900 330.630 ;
    END
  END w0_wd_in[12]
  PIN w0_wd_in[13]
    DIRECTION INPUT ;
    USE SIGNAL ;
    SHAPE ABUTMENT ;
    PORT
      LAYER met3 ;
      RECT 0.000 335.770 0.900 336.070 ;
    END
  END w0_wd_in[13]
  PIN w0_wd_in[14]
    DIRECTION INPUT ;
    USE SIGNAL ;
    SHAPE ABUTMENT ;
    PORT
      LAYER met3 ;
      RECT 0.000 341.210 0.900 341.510 ;
    END
  END w0_wd_in[14]
  PIN w0_wd_in[15]
    DIRECTION INPUT ;
    USE SIGNAL ;
    SHAPE ABUTMENT ;
    PORT
      LAYER met3 ;
      RECT 0.000 346.650 0.900 346.950 ;
    END
  END w0_wd_in[15]
  PIN w0_wd_in[16]
    DIRECTION INPUT ;
    USE SIGNAL ;
    SHAPE ABUTMENT ;
    PORT
      LAYER met3 ;
      RECT 0.000 352.090 0.900 352.390 ;
    END
  END w0_wd_in[16]
  PIN w0_wd_in[17]
    DIRECTION INPUT ;
    USE SIGNAL ;
    SHAPE ABUTMENT ;
    PORT
      LAYER met3 ;
      RECT 0.000 357.530 0.900 357.830 ;
    END
  END w0_wd_in[17]
  PIN w0_wd_in[18]
    DIRECTION INPUT ;
    USE SIGNAL ;
    SHAPE ABUTMENT ;
    PORT
      LAYER met3 ;
      RECT 0.000 362.970 0.900 363.270 ;
    END
  END w0_wd_in[18]
  PIN w0_wd_in[19]
    DIRECTION INPUT ;
    USE SIGNAL ;
    SHAPE ABUTMENT ;
    PORT
      LAYER met3 ;
      RECT 0.000 368.410 0.900 368.710 ;
    END
  END w0_wd_in[19]
  PIN w0_wd_in[20]
    DIRECTION INPUT ;
    USE SIGNAL ;
    SHAPE ABUTMENT ;
    PORT
      LAYER met3 ;
      RECT 0.000 373.850 0.900 374.150 ;
    END
  END w0_wd_in[20]
  PIN w0_wd_in[21]
    DIRECTION INPUT ;
    USE SIGNAL ;
    SHAPE ABUTMENT ;
    PORT
      LAYER met3 ;
      RECT 0.000 379.290 0.900 379.590 ;
    END
  END w0_wd_in[21]
  PIN w0_wd_in[22]
    DIRECTION INPUT ;
    USE SIGNAL ;
    SHAPE ABUTMENT ;
    PORT
      LAYER met3 ;
      RECT 0.000 384.730 0.900 385.030 ;
    END
  END w0_wd_in[22]
  PIN w0_wd_in[23]
    DIRECTION INPUT ;
    USE SIGNAL ;
    SHAPE ABUTMENT ;
    PORT
      LAYER met3 ;
      RECT 0.000 390.170 0.900 390.470 ;
    END
  END w0_wd_in[23]
  PIN w0_wd_in[24]
    DIRECTION INPUT ;
    USE SIGNAL ;
    SHAPE ABUTMENT ;
    PORT
      LAYER met3 ;
      RECT 0.000 395.610 0.900 395.910 ;
    END
  END w0_wd_in[24]
  PIN w0_wd_in[25]
    DIRECTION INPUT ;
    USE SIGNAL ;
    SHAPE ABUTMENT ;
    PORT
      LAYER met3 ;
      RECT 0.000 401.050 0.900 401.350 ;
    END
  END w0_wd_in[25]
  PIN w0_wd_in[26]
    DIRECTION INPUT ;
    USE SIGNAL ;
    SHAPE ABUTMENT ;
    PORT
      LAYER met3 ;
      RECT 0.000 406.490 0.900 406.790 ;
    END
  END w0_wd_in[26]
  PIN w0_wd_in[27]
    DIRECTION INPUT ;
    USE SIGNAL ;
    SHAPE ABUTMENT ;
    PORT
      LAYER met3 ;
      RECT 0.000 411.930 0.900 412.230 ;
    END
  END w0_wd_in[27]
  PIN w0_wd_in[28]
    DIRECTION INPUT ;
    USE SIGNAL ;
    SHAPE ABUTMENT ;
    PORT
      LAYER met3 ;
      RECT 0.000 417.370 0.900 417.670 ;
    END
  END w0_wd_in[28]
  PIN w0_wd_in[29]
    DIRECTION INPUT ;
    USE SIGNAL ;
    SHAPE ABUTMENT ;
    PORT
      LAYER met3 ;
      RECT 0.000 422.810 0.900 423.110 ;
    END
  END w0_wd_in[29]
  PIN w0_wd_in[30]
    DIRECTION INPUT ;
    USE SIGNAL ;
    SHAPE ABUTMENT ;
    PORT
      LAYER met3 ;
      RECT 0.000 428.250 0.900 428.550 ;
    END
  END w0_wd_in[30]
  PIN w0_wd_in[31]
    DIRECTION INPUT ;
    USE SIGNAL ;
    SHAPE ABUTMENT ;
    PORT
      LAYER met3 ;
      RECT 0.000 433.690 0.900 433.990 ;
    END
  END w0_wd_in[31]
  PIN w0_wd_in[32]
    DIRECTION INPUT ;
    USE SIGNAL ;
    SHAPE ABUTMENT ;
    PORT
      LAYER met3 ;
      RECT 0.000 439.130 0.900 439.430 ;
    END
  END w0_wd_in[32]
  PIN w0_wd_in[33]
    DIRECTION INPUT ;
    USE SIGNAL ;
    SHAPE ABUTMENT ;
    PORT
      LAYER met3 ;
      RECT 0.000 444.570 0.900 444.870 ;
    END
  END w0_wd_in[33]
  PIN w0_wd_in[34]
    DIRECTION INPUT ;
    USE SIGNAL ;
    SHAPE ABUTMENT ;
    PORT
      LAYER met3 ;
      RECT 0.000 450.010 0.900 450.310 ;
    END
  END w0_wd_in[34]
  PIN w0_wd_in[35]
    DIRECTION INPUT ;
    USE SIGNAL ;
    SHAPE ABUTMENT ;
    PORT
      LAYER met3 ;
      RECT 0.000 455.450 0.900 455.750 ;
    END
  END w0_wd_in[35]
  PIN w0_wd_in[36]
    DIRECTION INPUT ;
    USE SIGNAL ;
    SHAPE ABUTMENT ;
    PORT
      LAYER met3 ;
      RECT 0.000 460.890 0.900 461.190 ;
    END
  END w0_wd_in[36]
  PIN w0_wd_in[37]
    DIRECTION INPUT ;
    USE SIGNAL ;
    SHAPE ABUTMENT ;
    PORT
      LAYER met3 ;
      RECT 0.000 466.330 0.900 466.630 ;
    END
  END w0_wd_in[37]
  PIN w0_wd_in[38]
    DIRECTION INPUT ;
    USE SIGNAL ;
    SHAPE ABUTMENT ;
    PORT
      LAYER met3 ;
      RECT 0.000 471.770 0.900 472.070 ;
    END
  END w0_wd_in[38]
  PIN w0_wd_in[39]
    DIRECTION INPUT ;
    USE SIGNAL ;
    SHAPE ABUTMENT ;
    PORT
      LAYER met3 ;
      RECT 0.000 477.210 0.900 477.510 ;
    END
  END w0_wd_in[39]
  PIN w0_wd_in[40]
    DIRECTION INPUT ;
    USE SIGNAL ;
    SHAPE ABUTMENT ;
    PORT
      LAYER met3 ;
      RECT 0.000 482.650 0.900 482.950 ;
    END
  END w0_wd_in[40]
  PIN w0_wd_in[41]
    DIRECTION INPUT ;
    USE SIGNAL ;
    SHAPE ABUTMENT ;
    PORT
      LAYER met3 ;
      RECT 0.000 488.090 0.900 488.390 ;
    END
  END w0_wd_in[41]
  PIN w0_wd_in[42]
    DIRECTION INPUT ;
    USE SIGNAL ;
    SHAPE ABUTMENT ;
    PORT
      LAYER met3 ;
      RECT 0.000 493.530 0.900 493.830 ;
    END
  END w0_wd_in[42]
  PIN w0_wd_in[43]
    DIRECTION INPUT ;
    USE SIGNAL ;
    SHAPE ABUTMENT ;
    PORT
      LAYER met3 ;
      RECT 0.000 498.970 0.900 499.270 ;
    END
  END w0_wd_in[43]
  PIN w0_wd_in[44]
    DIRECTION INPUT ;
    USE SIGNAL ;
    SHAPE ABUTMENT ;
    PORT
      LAYER met3 ;
      RECT 0.000 504.410 0.900 504.710 ;
    END
  END w0_wd_in[44]
  PIN w0_wd_in[45]
    DIRECTION INPUT ;
    USE SIGNAL ;
    SHAPE ABUTMENT ;
    PORT
      LAYER met3 ;
      RECT 0.000 509.850 0.900 510.150 ;
    END
  END w0_wd_in[45]
  PIN w0_wd_in[46]
    DIRECTION INPUT ;
    USE SIGNAL ;
    SHAPE ABUTMENT ;
    PORT
      LAYER met3 ;
      RECT 0.000 515.290 0.900 515.590 ;
    END
  END w0_wd_in[46]
  PIN w0_wd_in[47]
    DIRECTION INPUT ;
    USE SIGNAL ;
    SHAPE ABUTMENT ;
    PORT
      LAYER met3 ;
      RECT 0.000 520.730 0.900 521.030 ;
    END
  END w0_wd_in[47]
  PIN w0_wd_in[48]
    DIRECTION INPUT ;
    USE SIGNAL ;
    SHAPE ABUTMENT ;
    PORT
      LAYER met3 ;
      RECT 341.340 265.050 342.240 265.350 ;
    END
  END w0_wd_in[48]
  PIN w0_wd_in[49]
    DIRECTION INPUT ;
    USE SIGNAL ;
    SHAPE ABUTMENT ;
    PORT
      LAYER met3 ;
      RECT 341.340 270.490 342.240 270.790 ;
    END
  END w0_wd_in[49]
  PIN w0_wd_in[50]
    DIRECTION INPUT ;
    USE SIGNAL ;
    SHAPE ABUTMENT ;
    PORT
      LAYER met3 ;
      RECT 341.340 275.930 342.240 276.230 ;
    END
  END w0_wd_in[50]
  PIN w0_wd_in[51]
    DIRECTION INPUT ;
    USE SIGNAL ;
    SHAPE ABUTMENT ;
    PORT
      LAYER met3 ;
      RECT 341.340 281.370 342.240 281.670 ;
    END
  END w0_wd_in[51]
  PIN w0_wd_in[52]
    DIRECTION INPUT ;
    USE SIGNAL ;
    SHAPE ABUTMENT ;
    PORT
      LAYER met3 ;
      RECT 341.340 286.810 342.240 287.110 ;
    END
  END w0_wd_in[52]
  PIN w0_wd_in[53]
    DIRECTION INPUT ;
    USE SIGNAL ;
    SHAPE ABUTMENT ;
    PORT
      LAYER met3 ;
      RECT 341.340 292.250 342.240 292.550 ;
    END
  END w0_wd_in[53]
  PIN w0_wd_in[54]
    DIRECTION INPUT ;
    USE SIGNAL ;
    SHAPE ABUTMENT ;
    PORT
      LAYER met3 ;
      RECT 341.340 297.690 342.240 297.990 ;
    END
  END w0_wd_in[54]
  PIN w0_wd_in[55]
    DIRECTION INPUT ;
    USE SIGNAL ;
    SHAPE ABUTMENT ;
    PORT
      LAYER met3 ;
      RECT 341.340 303.130 342.240 303.430 ;
    END
  END w0_wd_in[55]
  PIN w0_wd_in[56]
    DIRECTION INPUT ;
    USE SIGNAL ;
    SHAPE ABUTMENT ;
    PORT
      LAYER met3 ;
      RECT 341.340 308.570 342.240 308.870 ;
    END
  END w0_wd_in[56]
  PIN w0_wd_in[57]
    DIRECTION INPUT ;
    USE SIGNAL ;
    SHAPE ABUTMENT ;
    PORT
      LAYER met3 ;
      RECT 341.340 314.010 342.240 314.310 ;
    END
  END w0_wd_in[57]
  PIN w0_wd_in[58]
    DIRECTION INPUT ;
    USE SIGNAL ;
    SHAPE ABUTMENT ;
    PORT
      LAYER met3 ;
      RECT 341.340 319.450 342.240 319.750 ;
    END
  END w0_wd_in[58]
  PIN w0_wd_in[59]
    DIRECTION INPUT ;
    USE SIGNAL ;
    SHAPE ABUTMENT ;
    PORT
      LAYER met3 ;
      RECT 341.340 324.890 342.240 325.190 ;
    END
  END w0_wd_in[59]
  PIN w0_wd_in[60]
    DIRECTION INPUT ;
    USE SIGNAL ;
    SHAPE ABUTMENT ;
    PORT
      LAYER met3 ;
      RECT 341.340 330.330 342.240 330.630 ;
    END
  END w0_wd_in[60]
  PIN w0_wd_in[61]
    DIRECTION INPUT ;
    USE SIGNAL ;
    SHAPE ABUTMENT ;
    PORT
      LAYER met3 ;
      RECT 341.340 335.770 342.240 336.070 ;
    END
  END w0_wd_in[61]
  PIN w0_wd_in[62]
    DIRECTION INPUT ;
    USE SIGNAL ;
    SHAPE ABUTMENT ;
    PORT
      LAYER met3 ;
      RECT 341.340 341.210 342.240 341.510 ;
    END
  END w0_wd_in[62]
  PIN w0_wd_in[63]
    DIRECTION INPUT ;
    USE SIGNAL ;
    SHAPE ABUTMENT ;
    PORT
      LAYER met3 ;
      RECT 341.340 346.650 342.240 346.950 ;
    END
  END w0_wd_in[63]
  PIN w0_wd_in[64]
    DIRECTION INPUT ;
    USE SIGNAL ;
    SHAPE ABUTMENT ;
    PORT
      LAYER met3 ;
      RECT 341.340 352.090 342.240 352.390 ;
    END
  END w0_wd_in[64]
  PIN w0_wd_in[65]
    DIRECTION INPUT ;
    USE SIGNAL ;
    SHAPE ABUTMENT ;
    PORT
      LAYER met3 ;
      RECT 341.340 357.530 342.240 357.830 ;
    END
  END w0_wd_in[65]
  PIN w0_wd_in[66]
    DIRECTION INPUT ;
    USE SIGNAL ;
    SHAPE ABUTMENT ;
    PORT
      LAYER met3 ;
      RECT 341.340 362.970 342.240 363.270 ;
    END
  END w0_wd_in[66]
  PIN w0_wd_in[67]
    DIRECTION INPUT ;
    USE SIGNAL ;
    SHAPE ABUTMENT ;
    PORT
      LAYER met3 ;
      RECT 341.340 368.410 342.240 368.710 ;
    END
  END w0_wd_in[67]
  PIN w0_wd_in[68]
    DIRECTION INPUT ;
    USE SIGNAL ;
    SHAPE ABUTMENT ;
    PORT
      LAYER met3 ;
      RECT 341.340 373.850 342.240 374.150 ;
    END
  END w0_wd_in[68]
  PIN w0_wd_in[69]
    DIRECTION INPUT ;
    USE SIGNAL ;
    SHAPE ABUTMENT ;
    PORT
      LAYER met3 ;
      RECT 341.340 379.290 342.240 379.590 ;
    END
  END w0_wd_in[69]
  PIN w0_wd_in[70]
    DIRECTION INPUT ;
    USE SIGNAL ;
    SHAPE ABUTMENT ;
    PORT
      LAYER met3 ;
      RECT 341.340 384.730 342.240 385.030 ;
    END
  END w0_wd_in[70]
  PIN w0_wd_in[71]
    DIRECTION INPUT ;
    USE SIGNAL ;
    SHAPE ABUTMENT ;
    PORT
      LAYER met3 ;
      RECT 341.340 390.170 342.240 390.470 ;
    END
  END w0_wd_in[71]
  PIN w0_wd_in[72]
    DIRECTION INPUT ;
    USE SIGNAL ;
    SHAPE ABUTMENT ;
    PORT
      LAYER met3 ;
      RECT 341.340 395.610 342.240 395.910 ;
    END
  END w0_wd_in[72]
  PIN w0_wd_in[73]
    DIRECTION INPUT ;
    USE SIGNAL ;
    SHAPE ABUTMENT ;
    PORT
      LAYER met3 ;
      RECT 341.340 401.050 342.240 401.350 ;
    END
  END w0_wd_in[73]
  PIN w0_wd_in[74]
    DIRECTION INPUT ;
    USE SIGNAL ;
    SHAPE ABUTMENT ;
    PORT
      LAYER met3 ;
      RECT 341.340 406.490 342.240 406.790 ;
    END
  END w0_wd_in[74]
  PIN w0_wd_in[75]
    DIRECTION INPUT ;
    USE SIGNAL ;
    SHAPE ABUTMENT ;
    PORT
      LAYER met3 ;
      RECT 341.340 411.930 342.240 412.230 ;
    END
  END w0_wd_in[75]
  PIN w0_wd_in[76]
    DIRECTION INPUT ;
    USE SIGNAL ;
    SHAPE ABUTMENT ;
    PORT
      LAYER met3 ;
      RECT 341.340 417.370 342.240 417.670 ;
    END
  END w0_wd_in[76]
  PIN w0_wd_in[77]
    DIRECTION INPUT ;
    USE SIGNAL ;
    SHAPE ABUTMENT ;
    PORT
      LAYER met3 ;
      RECT 341.340 422.810 342.240 423.110 ;
    END
  END w0_wd_in[77]
  PIN w0_wd_in[78]
    DIRECTION INPUT ;
    USE SIGNAL ;
    SHAPE ABUTMENT ;
    PORT
      LAYER met3 ;
      RECT 341.340 428.250 342.240 428.550 ;
    END
  END w0_wd_in[78]
  PIN w0_wd_in[79]
    DIRECTION INPUT ;
    USE SIGNAL ;
    SHAPE ABUTMENT ;
    PORT
      LAYER met3 ;
      RECT 341.340 433.690 342.240 433.990 ;
    END
  END w0_wd_in[79]
  PIN w0_wd_in[80]
    DIRECTION INPUT ;
    USE SIGNAL ;
    SHAPE ABUTMENT ;
    PORT
      LAYER met3 ;
      RECT 341.340 439.130 342.240 439.430 ;
    END
  END w0_wd_in[80]
  PIN w0_wd_in[81]
    DIRECTION INPUT ;
    USE SIGNAL ;
    SHAPE ABUTMENT ;
    PORT
      LAYER met3 ;
      RECT 341.340 444.570 342.240 444.870 ;
    END
  END w0_wd_in[81]
  PIN w0_wd_in[82]
    DIRECTION INPUT ;
    USE SIGNAL ;
    SHAPE ABUTMENT ;
    PORT
      LAYER met3 ;
      RECT 341.340 450.010 342.240 450.310 ;
    END
  END w0_wd_in[82]
  PIN w0_wd_in[83]
    DIRECTION INPUT ;
    USE SIGNAL ;
    SHAPE ABUTMENT ;
    PORT
      LAYER met3 ;
      RECT 341.340 455.450 342.240 455.750 ;
    END
  END w0_wd_in[83]
  PIN w0_wd_in[84]
    DIRECTION INPUT ;
    USE SIGNAL ;
    SHAPE ABUTMENT ;
    PORT
      LAYER met3 ;
      RECT 341.340 460.890 342.240 461.190 ;
    END
  END w0_wd_in[84]
  PIN w0_wd_in[85]
    DIRECTION INPUT ;
    USE SIGNAL ;
    SHAPE ABUTMENT ;
    PORT
      LAYER met3 ;
      RECT 341.340 466.330 342.240 466.630 ;
    END
  END w0_wd_in[85]
  PIN w0_wd_in[86]
    DIRECTION INPUT ;
    USE SIGNAL ;
    SHAPE ABUTMENT ;
    PORT
      LAYER met3 ;
      RECT 341.340 471.770 342.240 472.070 ;
    END
  END w0_wd_in[86]
  PIN w0_wd_in[87]
    DIRECTION INPUT ;
    USE SIGNAL ;
    SHAPE ABUTMENT ;
    PORT
      LAYER met3 ;
      RECT 341.340 477.210 342.240 477.510 ;
    END
  END w0_wd_in[87]
  PIN w0_wd_in[88]
    DIRECTION INPUT ;
    USE SIGNAL ;
    SHAPE ABUTMENT ;
    PORT
      LAYER met3 ;
      RECT 341.340 482.650 342.240 482.950 ;
    END
  END w0_wd_in[88]
  PIN w0_wd_in[89]
    DIRECTION INPUT ;
    USE SIGNAL ;
    SHAPE ABUTMENT ;
    PORT
      LAYER met3 ;
      RECT 341.340 488.090 342.240 488.390 ;
    END
  END w0_wd_in[89]
  PIN w0_wd_in[90]
    DIRECTION INPUT ;
    USE SIGNAL ;
    SHAPE ABUTMENT ;
    PORT
      LAYER met3 ;
      RECT 341.340 493.530 342.240 493.830 ;
    END
  END w0_wd_in[90]
  PIN w0_wd_in[91]
    DIRECTION INPUT ;
    USE SIGNAL ;
    SHAPE ABUTMENT ;
    PORT
      LAYER met3 ;
      RECT 341.340 498.970 342.240 499.270 ;
    END
  END w0_wd_in[91]
  PIN w0_wd_in[92]
    DIRECTION INPUT ;
    USE SIGNAL ;
    SHAPE ABUTMENT ;
    PORT
      LAYER met3 ;
      RECT 341.340 504.410 342.240 504.710 ;
    END
  END w0_wd_in[92]
  PIN w0_wd_in[93]
    DIRECTION INPUT ;
    USE SIGNAL ;
    SHAPE ABUTMENT ;
    PORT
      LAYER met3 ;
      RECT 341.340 509.850 342.240 510.150 ;
    END
  END w0_wd_in[93]
  PIN w0_wd_in[94]
    DIRECTION INPUT ;
    USE SIGNAL ;
    SHAPE ABUTMENT ;
    PORT
      LAYER met3 ;
      RECT 341.340 515.290 342.240 515.590 ;
    END
  END w0_wd_in[94]
  PIN w0_wd_in[95]
    DIRECTION INPUT ;
    USE SIGNAL ;
    SHAPE ABUTMENT ;
    PORT
      LAYER met3 ;
      RECT 341.340 520.730 342.240 521.030 ;
    END
  END w0_wd_in[95]
  PIN w0_wd_in[96]
    DIRECTION OUTPUT ;
    USE SIGNAL ;
    SHAPE ABUTMENT ;
    PORT
      LAYER met2 ;
      RECT 2.690 0.000 2.830 0.420 ;
    END
  END w0_wd_in[96]
  PIN w0_wd_in[97]
    DIRECTION OUTPUT ;
    USE SIGNAL ;
    SHAPE ABUTMENT ;
    PORT
      LAYER met2 ;
      RECT 4.070 0.000 4.210 0.420 ;
    END
  END w0_wd_in[97]
  PIN w0_wd_in[98]
    DIRECTION OUTPUT ;
    USE SIGNAL ;
    SHAPE ABUTMENT ;
    PORT
      LAYER met2 ;
      RECT 5.450 0.000 5.590 0.420 ;
    END
  END w0_wd_in[98]
  PIN w0_wd_in[99]
    DIRECTION OUTPUT ;
    USE SIGNAL ;
    SHAPE ABUTMENT ;
    PORT
      LAYER met2 ;
      RECT 6.830 0.000 6.970 0.420 ;
    END
  END w0_wd_in[99]
  PIN w0_wd_in[100]
    DIRECTION OUTPUT ;
    USE SIGNAL ;
    SHAPE ABUTMENT ;
    PORT
      LAYER met2 ;
      RECT 8.210 0.000 8.350 0.420 ;
    END
  END w0_wd_in[100]
  PIN w0_wd_in[101]
    DIRECTION OUTPUT ;
    USE SIGNAL ;
    SHAPE ABUTMENT ;
    PORT
      LAYER met2 ;
      RECT 9.590 0.000 9.730 0.420 ;
    END
  END w0_wd_in[101]
  PIN w0_wd_in[102]
    DIRECTION OUTPUT ;
    USE SIGNAL ;
    SHAPE ABUTMENT ;
    PORT
      LAYER met2 ;
      RECT 10.970 0.000 11.110 0.420 ;
    END
  END w0_wd_in[102]
  PIN w0_wd_in[103]
    DIRECTION OUTPUT ;
    USE SIGNAL ;
    SHAPE ABUTMENT ;
    PORT
      LAYER met2 ;
      RECT 12.350 0.000 12.490 0.420 ;
    END
  END w0_wd_in[103]
  PIN w0_wd_in[104]
    DIRECTION OUTPUT ;
    USE SIGNAL ;
    SHAPE ABUTMENT ;
    PORT
      LAYER met2 ;
      RECT 13.730 0.000 13.870 0.420 ;
    END
  END w0_wd_in[104]
  PIN w0_wd_in[105]
    DIRECTION OUTPUT ;
    USE SIGNAL ;
    SHAPE ABUTMENT ;
    PORT
      LAYER met2 ;
      RECT 15.110 0.000 15.250 0.420 ;
    END
  END w0_wd_in[105]
  PIN w0_wd_in[106]
    DIRECTION OUTPUT ;
    USE SIGNAL ;
    SHAPE ABUTMENT ;
    PORT
      LAYER met2 ;
      RECT 16.490 0.000 16.630 0.420 ;
    END
  END w0_wd_in[106]
  PIN w0_wd_in[107]
    DIRECTION OUTPUT ;
    USE SIGNAL ;
    SHAPE ABUTMENT ;
    PORT
      LAYER met2 ;
      RECT 17.870 0.000 18.010 0.420 ;
    END
  END w0_wd_in[107]
  PIN w0_wd_in[108]
    DIRECTION OUTPUT ;
    USE SIGNAL ;
    SHAPE ABUTMENT ;
    PORT
      LAYER met2 ;
      RECT 19.250 0.000 19.390 0.420 ;
    END
  END w0_wd_in[108]
  PIN w0_wd_in[109]
    DIRECTION OUTPUT ;
    USE SIGNAL ;
    SHAPE ABUTMENT ;
    PORT
      LAYER met2 ;
      RECT 20.630 0.000 20.770 0.420 ;
    END
  END w0_wd_in[109]
  PIN w0_wd_in[110]
    DIRECTION OUTPUT ;
    USE SIGNAL ;
    SHAPE ABUTMENT ;
    PORT
      LAYER met2 ;
      RECT 22.010 0.000 22.150 0.420 ;
    END
  END w0_wd_in[110]
  PIN w0_wd_in[111]
    DIRECTION OUTPUT ;
    USE SIGNAL ;
    SHAPE ABUTMENT ;
    PORT
      LAYER met2 ;
      RECT 23.390 0.000 23.530 0.420 ;
    END
  END w0_wd_in[111]
  PIN w0_wd_in[112]
    DIRECTION OUTPUT ;
    USE SIGNAL ;
    SHAPE ABUTMENT ;
    PORT
      LAYER met2 ;
      RECT 24.770 0.000 24.910 0.420 ;
    END
  END w0_wd_in[112]
  PIN w0_wd_in[113]
    DIRECTION OUTPUT ;
    USE SIGNAL ;
    SHAPE ABUTMENT ;
    PORT
      LAYER met2 ;
      RECT 26.150 0.000 26.290 0.420 ;
    END
  END w0_wd_in[113]
  PIN w0_wd_in[114]
    DIRECTION OUTPUT ;
    USE SIGNAL ;
    SHAPE ABUTMENT ;
    PORT
      LAYER met2 ;
      RECT 27.530 0.000 27.670 0.420 ;
    END
  END w0_wd_in[114]
  PIN w0_wd_in[115]
    DIRECTION OUTPUT ;
    USE SIGNAL ;
    SHAPE ABUTMENT ;
    PORT
      LAYER met2 ;
      RECT 28.910 0.000 29.050 0.420 ;
    END
  END w0_wd_in[115]
  PIN w0_wd_in[116]
    DIRECTION OUTPUT ;
    USE SIGNAL ;
    SHAPE ABUTMENT ;
    PORT
      LAYER met2 ;
      RECT 30.290 0.000 30.430 0.420 ;
    END
  END w0_wd_in[116]
  PIN w0_wd_in[117]
    DIRECTION OUTPUT ;
    USE SIGNAL ;
    SHAPE ABUTMENT ;
    PORT
      LAYER met2 ;
      RECT 31.670 0.000 31.810 0.420 ;
    END
  END w0_wd_in[117]
  PIN w0_wd_in[118]
    DIRECTION OUTPUT ;
    USE SIGNAL ;
    SHAPE ABUTMENT ;
    PORT
      LAYER met2 ;
      RECT 33.050 0.000 33.190 0.420 ;
    END
  END w0_wd_in[118]
  PIN w0_wd_in[119]
    DIRECTION OUTPUT ;
    USE SIGNAL ;
    SHAPE ABUTMENT ;
    PORT
      LAYER met2 ;
      RECT 34.430 0.000 34.570 0.420 ;
    END
  END w0_wd_in[119]
  PIN w0_wd_in[120]
    DIRECTION OUTPUT ;
    USE SIGNAL ;
    SHAPE ABUTMENT ;
    PORT
      LAYER met2 ;
      RECT 35.810 0.000 35.950 0.420 ;
    END
  END w0_wd_in[120]
  PIN w0_wd_in[121]
    DIRECTION OUTPUT ;
    USE SIGNAL ;
    SHAPE ABUTMENT ;
    PORT
      LAYER met2 ;
      RECT 37.190 0.000 37.330 0.420 ;
    END
  END w0_wd_in[121]
  PIN w0_wd_in[122]
    DIRECTION OUTPUT ;
    USE SIGNAL ;
    SHAPE ABUTMENT ;
    PORT
      LAYER met2 ;
      RECT 38.570 0.000 38.710 0.420 ;
    END
  END w0_wd_in[122]
  PIN w0_wd_in[123]
    DIRECTION OUTPUT ;
    USE SIGNAL ;
    SHAPE ABUTMENT ;
    PORT
      LAYER met2 ;
      RECT 39.950 0.000 40.090 0.420 ;
    END
  END w0_wd_in[123]
  PIN w0_wd_in[124]
    DIRECTION OUTPUT ;
    USE SIGNAL ;
    SHAPE ABUTMENT ;
    PORT
      LAYER met2 ;
      RECT 41.330 0.000 41.470 0.420 ;
    END
  END w0_wd_in[124]
  PIN w0_wd_in[125]
    DIRECTION OUTPUT ;
    USE SIGNAL ;
    SHAPE ABUTMENT ;
    PORT
      LAYER met2 ;
      RECT 42.710 0.000 42.850 0.420 ;
    END
  END w0_wd_in[125]
  PIN w0_wd_in[126]
    DIRECTION OUTPUT ;
    USE SIGNAL ;
    SHAPE ABUTMENT ;
    PORT
      LAYER met2 ;
      RECT 44.090 0.000 44.230 0.420 ;
    END
  END w0_wd_in[126]
  PIN w0_wd_in[127]
    DIRECTION OUTPUT ;
    USE SIGNAL ;
    SHAPE ABUTMENT ;
    PORT
      LAYER met2 ;
      RECT 45.470 0.000 45.610 0.420 ;
    END
  END w0_wd_in[127]
  PIN w0_wd_in[128]
    DIRECTION OUTPUT ;
    USE SIGNAL ;
    SHAPE ABUTMENT ;
    PORT
      LAYER met2 ;
      RECT 46.850 0.000 46.990 0.420 ;
    END
  END w0_wd_in[128]
  PIN w0_wd_in[129]
    DIRECTION OUTPUT ;
    USE SIGNAL ;
    SHAPE ABUTMENT ;
    PORT
      LAYER met2 ;
      RECT 48.230 0.000 48.370 0.420 ;
    END
  END w0_wd_in[129]
  PIN w0_wd_in[130]
    DIRECTION OUTPUT ;
    USE SIGNAL ;
    SHAPE ABUTMENT ;
    PORT
      LAYER met2 ;
      RECT 49.610 0.000 49.750 0.420 ;
    END
  END w0_wd_in[130]
  PIN w0_wd_in[131]
    DIRECTION OUTPUT ;
    USE SIGNAL ;
    SHAPE ABUTMENT ;
    PORT
      LAYER met2 ;
      RECT 50.990 0.000 51.130 0.420 ;
    END
  END w0_wd_in[131]
  PIN w0_wd_in[132]
    DIRECTION OUTPUT ;
    USE SIGNAL ;
    SHAPE ABUTMENT ;
    PORT
      LAYER met2 ;
      RECT 52.370 0.000 52.510 0.420 ;
    END
  END w0_wd_in[132]
  PIN w0_wd_in[133]
    DIRECTION OUTPUT ;
    USE SIGNAL ;
    SHAPE ABUTMENT ;
    PORT
      LAYER met2 ;
      RECT 53.750 0.000 53.890 0.420 ;
    END
  END w0_wd_in[133]
  PIN w0_wd_in[134]
    DIRECTION OUTPUT ;
    USE SIGNAL ;
    SHAPE ABUTMENT ;
    PORT
      LAYER met2 ;
      RECT 55.130 0.000 55.270 0.420 ;
    END
  END w0_wd_in[134]
  PIN w0_wd_in[135]
    DIRECTION OUTPUT ;
    USE SIGNAL ;
    SHAPE ABUTMENT ;
    PORT
      LAYER met2 ;
      RECT 56.510 0.000 56.650 0.420 ;
    END
  END w0_wd_in[135]
  PIN w0_wd_in[136]
    DIRECTION OUTPUT ;
    USE SIGNAL ;
    SHAPE ABUTMENT ;
    PORT
      LAYER met2 ;
      RECT 57.890 0.000 58.030 0.420 ;
    END
  END w0_wd_in[136]
  PIN w0_wd_in[137]
    DIRECTION OUTPUT ;
    USE SIGNAL ;
    SHAPE ABUTMENT ;
    PORT
      LAYER met2 ;
      RECT 59.270 0.000 59.410 0.420 ;
    END
  END w0_wd_in[137]
  PIN w0_wd_in[138]
    DIRECTION OUTPUT ;
    USE SIGNAL ;
    SHAPE ABUTMENT ;
    PORT
      LAYER met2 ;
      RECT 60.650 0.000 60.790 0.420 ;
    END
  END w0_wd_in[138]
  PIN w0_wd_in[139]
    DIRECTION OUTPUT ;
    USE SIGNAL ;
    SHAPE ABUTMENT ;
    PORT
      LAYER met2 ;
      RECT 62.030 0.000 62.170 0.420 ;
    END
  END w0_wd_in[139]
  PIN w0_wd_in[140]
    DIRECTION OUTPUT ;
    USE SIGNAL ;
    SHAPE ABUTMENT ;
    PORT
      LAYER met2 ;
      RECT 63.410 0.000 63.550 0.420 ;
    END
  END w0_wd_in[140]
  PIN w0_wd_in[141]
    DIRECTION OUTPUT ;
    USE SIGNAL ;
    SHAPE ABUTMENT ;
    PORT
      LAYER met2 ;
      RECT 64.790 0.000 64.930 0.420 ;
    END
  END w0_wd_in[141]
  PIN w0_wd_in[142]
    DIRECTION OUTPUT ;
    USE SIGNAL ;
    SHAPE ABUTMENT ;
    PORT
      LAYER met2 ;
      RECT 66.170 0.000 66.310 0.420 ;
    END
  END w0_wd_in[142]
  PIN w0_wd_in[143]
    DIRECTION OUTPUT ;
    USE SIGNAL ;
    SHAPE ABUTMENT ;
    PORT
      LAYER met2 ;
      RECT 67.550 0.000 67.690 0.420 ;
    END
  END w0_wd_in[143]
  PIN w0_wd_in[144]
    DIRECTION OUTPUT ;
    USE SIGNAL ;
    SHAPE ABUTMENT ;
    PORT
      LAYER met2 ;
      RECT 68.930 0.000 69.070 0.420 ;
    END
  END w0_wd_in[144]
  PIN w0_wd_in[145]
    DIRECTION OUTPUT ;
    USE SIGNAL ;
    SHAPE ABUTMENT ;
    PORT
      LAYER met2 ;
      RECT 70.310 0.000 70.450 0.420 ;
    END
  END w0_wd_in[145]
  PIN w0_wd_in[146]
    DIRECTION OUTPUT ;
    USE SIGNAL ;
    SHAPE ABUTMENT ;
    PORT
      LAYER met2 ;
      RECT 71.690 0.000 71.830 0.420 ;
    END
  END w0_wd_in[146]
  PIN w0_wd_in[147]
    DIRECTION OUTPUT ;
    USE SIGNAL ;
    SHAPE ABUTMENT ;
    PORT
      LAYER met2 ;
      RECT 73.070 0.000 73.210 0.420 ;
    END
  END w0_wd_in[147]
  PIN w0_wd_in[148]
    DIRECTION OUTPUT ;
    USE SIGNAL ;
    SHAPE ABUTMENT ;
    PORT
      LAYER met2 ;
      RECT 74.450 0.000 74.590 0.420 ;
    END
  END w0_wd_in[148]
  PIN w0_wd_in[149]
    DIRECTION OUTPUT ;
    USE SIGNAL ;
    SHAPE ABUTMENT ;
    PORT
      LAYER met2 ;
      RECT 75.830 0.000 75.970 0.420 ;
    END
  END w0_wd_in[149]
  PIN w0_wd_in[150]
    DIRECTION OUTPUT ;
    USE SIGNAL ;
    SHAPE ABUTMENT ;
    PORT
      LAYER met2 ;
      RECT 77.210 0.000 77.350 0.420 ;
    END
  END w0_wd_in[150]
  PIN w0_wd_in[151]
    DIRECTION OUTPUT ;
    USE SIGNAL ;
    SHAPE ABUTMENT ;
    PORT
      LAYER met2 ;
      RECT 78.590 0.000 78.730 0.420 ;
    END
  END w0_wd_in[151]
  PIN w0_wd_in[152]
    DIRECTION OUTPUT ;
    USE SIGNAL ;
    SHAPE ABUTMENT ;
    PORT
      LAYER met2 ;
      RECT 79.970 0.000 80.110 0.420 ;
    END
  END w0_wd_in[152]
  PIN w0_wd_in[153]
    DIRECTION OUTPUT ;
    USE SIGNAL ;
    SHAPE ABUTMENT ;
    PORT
      LAYER met2 ;
      RECT 81.350 0.000 81.490 0.420 ;
    END
  END w0_wd_in[153]
  PIN w0_wd_in[154]
    DIRECTION OUTPUT ;
    USE SIGNAL ;
    SHAPE ABUTMENT ;
    PORT
      LAYER met2 ;
      RECT 82.730 0.000 82.870 0.420 ;
    END
  END w0_wd_in[154]
  PIN w0_wd_in[155]
    DIRECTION OUTPUT ;
    USE SIGNAL ;
    SHAPE ABUTMENT ;
    PORT
      LAYER met2 ;
      RECT 84.110 0.000 84.250 0.420 ;
    END
  END w0_wd_in[155]
  PIN w0_wd_in[156]
    DIRECTION OUTPUT ;
    USE SIGNAL ;
    SHAPE ABUTMENT ;
    PORT
      LAYER met2 ;
      RECT 85.490 0.000 85.630 0.420 ;
    END
  END w0_wd_in[156]
  PIN w0_wd_in[157]
    DIRECTION OUTPUT ;
    USE SIGNAL ;
    SHAPE ABUTMENT ;
    PORT
      LAYER met2 ;
      RECT 86.870 0.000 87.010 0.420 ;
    END
  END w0_wd_in[157]
  PIN w0_wd_in[158]
    DIRECTION OUTPUT ;
    USE SIGNAL ;
    SHAPE ABUTMENT ;
    PORT
      LAYER met2 ;
      RECT 88.250 0.000 88.390 0.420 ;
    END
  END w0_wd_in[158]
  PIN w0_wd_in[159]
    DIRECTION OUTPUT ;
    USE SIGNAL ;
    SHAPE ABUTMENT ;
    PORT
      LAYER met2 ;
      RECT 89.630 0.000 89.770 0.420 ;
    END
  END w0_wd_in[159]
  PIN w0_wd_in[160]
    DIRECTION OUTPUT ;
    USE SIGNAL ;
    SHAPE ABUTMENT ;
    PORT
      LAYER met2 ;
      RECT 91.010 0.000 91.150 0.420 ;
    END
  END w0_wd_in[160]
  PIN w0_wd_in[161]
    DIRECTION OUTPUT ;
    USE SIGNAL ;
    SHAPE ABUTMENT ;
    PORT
      LAYER met2 ;
      RECT 92.390 0.000 92.530 0.420 ;
    END
  END w0_wd_in[161]
  PIN w0_wd_in[162]
    DIRECTION OUTPUT ;
    USE SIGNAL ;
    SHAPE ABUTMENT ;
    PORT
      LAYER met2 ;
      RECT 93.770 0.000 93.910 0.420 ;
    END
  END w0_wd_in[162]
  PIN w0_wd_in[163]
    DIRECTION OUTPUT ;
    USE SIGNAL ;
    SHAPE ABUTMENT ;
    PORT
      LAYER met2 ;
      RECT 95.150 0.000 95.290 0.420 ;
    END
  END w0_wd_in[163]
  PIN w0_wd_in[164]
    DIRECTION OUTPUT ;
    USE SIGNAL ;
    SHAPE ABUTMENT ;
    PORT
      LAYER met2 ;
      RECT 96.530 0.000 96.670 0.420 ;
    END
  END w0_wd_in[164]
  PIN w0_wd_in[165]
    DIRECTION OUTPUT ;
    USE SIGNAL ;
    SHAPE ABUTMENT ;
    PORT
      LAYER met2 ;
      RECT 97.910 0.000 98.050 0.420 ;
    END
  END w0_wd_in[165]
  PIN w0_wd_in[166]
    DIRECTION OUTPUT ;
    USE SIGNAL ;
    SHAPE ABUTMENT ;
    PORT
      LAYER met2 ;
      RECT 99.290 0.000 99.430 0.420 ;
    END
  END w0_wd_in[166]
  PIN w0_wd_in[167]
    DIRECTION OUTPUT ;
    USE SIGNAL ;
    SHAPE ABUTMENT ;
    PORT
      LAYER met2 ;
      RECT 100.670 0.000 100.810 0.420 ;
    END
  END w0_wd_in[167]
  PIN w0_wd_in[168]
    DIRECTION OUTPUT ;
    USE SIGNAL ;
    SHAPE ABUTMENT ;
    PORT
      LAYER met2 ;
      RECT 102.050 0.000 102.190 0.420 ;
    END
  END w0_wd_in[168]
  PIN w0_wd_in[169]
    DIRECTION OUTPUT ;
    USE SIGNAL ;
    SHAPE ABUTMENT ;
    PORT
      LAYER met2 ;
      RECT 103.430 0.000 103.570 0.420 ;
    END
  END w0_wd_in[169]
  PIN w0_wd_in[170]
    DIRECTION OUTPUT ;
    USE SIGNAL ;
    SHAPE ABUTMENT ;
    PORT
      LAYER met2 ;
      RECT 104.810 0.000 104.950 0.420 ;
    END
  END w0_wd_in[170]
  PIN w0_wd_in[171]
    DIRECTION OUTPUT ;
    USE SIGNAL ;
    SHAPE ABUTMENT ;
    PORT
      LAYER met2 ;
      RECT 106.190 0.000 106.330 0.420 ;
    END
  END w0_wd_in[171]
  PIN w0_wd_in[172]
    DIRECTION OUTPUT ;
    USE SIGNAL ;
    SHAPE ABUTMENT ;
    PORT
      LAYER met2 ;
      RECT 107.570 0.000 107.710 0.420 ;
    END
  END w0_wd_in[172]
  PIN w0_wd_in[173]
    DIRECTION OUTPUT ;
    USE SIGNAL ;
    SHAPE ABUTMENT ;
    PORT
      LAYER met2 ;
      RECT 108.950 0.000 109.090 0.420 ;
    END
  END w0_wd_in[173]
  PIN w0_wd_in[174]
    DIRECTION OUTPUT ;
    USE SIGNAL ;
    SHAPE ABUTMENT ;
    PORT
      LAYER met2 ;
      RECT 110.330 0.000 110.470 0.420 ;
    END
  END w0_wd_in[174]
  PIN w0_wd_in[175]
    DIRECTION OUTPUT ;
    USE SIGNAL ;
    SHAPE ABUTMENT ;
    PORT
      LAYER met2 ;
      RECT 111.710 0.000 111.850 0.420 ;
    END
  END w0_wd_in[175]
  PIN w0_wd_in[176]
    DIRECTION OUTPUT ;
    USE SIGNAL ;
    SHAPE ABUTMENT ;
    PORT
      LAYER met2 ;
      RECT 113.090 0.000 113.230 0.420 ;
    END
  END w0_wd_in[176]
  PIN w0_wd_in[177]
    DIRECTION OUTPUT ;
    USE SIGNAL ;
    SHAPE ABUTMENT ;
    PORT
      LAYER met2 ;
      RECT 114.470 0.000 114.610 0.420 ;
    END
  END w0_wd_in[177]
  PIN w0_wd_in[178]
    DIRECTION OUTPUT ;
    USE SIGNAL ;
    SHAPE ABUTMENT ;
    PORT
      LAYER met2 ;
      RECT 115.850 0.000 115.990 0.420 ;
    END
  END w0_wd_in[178]
  PIN w0_wd_in[179]
    DIRECTION OUTPUT ;
    USE SIGNAL ;
    SHAPE ABUTMENT ;
    PORT
      LAYER met2 ;
      RECT 117.230 0.000 117.370 0.420 ;
    END
  END w0_wd_in[179]
  PIN w0_wd_in[180]
    DIRECTION OUTPUT ;
    USE SIGNAL ;
    SHAPE ABUTMENT ;
    PORT
      LAYER met2 ;
      RECT 118.610 0.000 118.750 0.420 ;
    END
  END w0_wd_in[180]
  PIN w0_wd_in[181]
    DIRECTION OUTPUT ;
    USE SIGNAL ;
    SHAPE ABUTMENT ;
    PORT
      LAYER met2 ;
      RECT 119.990 0.000 120.130 0.420 ;
    END
  END w0_wd_in[181]
  PIN w0_wd_in[182]
    DIRECTION OUTPUT ;
    USE SIGNAL ;
    SHAPE ABUTMENT ;
    PORT
      LAYER met2 ;
      RECT 121.370 0.000 121.510 0.420 ;
    END
  END w0_wd_in[182]
  PIN w0_wd_in[183]
    DIRECTION OUTPUT ;
    USE SIGNAL ;
    SHAPE ABUTMENT ;
    PORT
      LAYER met2 ;
      RECT 122.750 0.000 122.890 0.420 ;
    END
  END w0_wd_in[183]
  PIN w0_wd_in[184]
    DIRECTION OUTPUT ;
    USE SIGNAL ;
    SHAPE ABUTMENT ;
    PORT
      LAYER met2 ;
      RECT 124.130 0.000 124.270 0.420 ;
    END
  END w0_wd_in[184]
  PIN w0_wd_in[185]
    DIRECTION OUTPUT ;
    USE SIGNAL ;
    SHAPE ABUTMENT ;
    PORT
      LAYER met2 ;
      RECT 125.510 0.000 125.650 0.420 ;
    END
  END w0_wd_in[185]
  PIN w0_wd_in[186]
    DIRECTION OUTPUT ;
    USE SIGNAL ;
    SHAPE ABUTMENT ;
    PORT
      LAYER met2 ;
      RECT 126.890 0.000 127.030 0.420 ;
    END
  END w0_wd_in[186]
  PIN w0_wd_in[187]
    DIRECTION OUTPUT ;
    USE SIGNAL ;
    SHAPE ABUTMENT ;
    PORT
      LAYER met2 ;
      RECT 128.270 0.000 128.410 0.420 ;
    END
  END w0_wd_in[187]
  PIN w0_wd_in[188]
    DIRECTION OUTPUT ;
    USE SIGNAL ;
    SHAPE ABUTMENT ;
    PORT
      LAYER met2 ;
      RECT 129.650 0.000 129.790 0.420 ;
    END
  END w0_wd_in[188]
  PIN w0_wd_in[189]
    DIRECTION OUTPUT ;
    USE SIGNAL ;
    SHAPE ABUTMENT ;
    PORT
      LAYER met2 ;
      RECT 131.030 0.000 131.170 0.420 ;
    END
  END w0_wd_in[189]
  PIN w0_wd_in[190]
    DIRECTION OUTPUT ;
    USE SIGNAL ;
    SHAPE ABUTMENT ;
    PORT
      LAYER met2 ;
      RECT 132.410 0.000 132.550 0.420 ;
    END
  END w0_wd_in[190]
  PIN w0_wd_in[191]
    DIRECTION OUTPUT ;
    USE SIGNAL ;
    SHAPE ABUTMENT ;
    PORT
      LAYER met2 ;
      RECT 133.790 0.000 133.930 0.420 ;
    END
  END w0_wd_in[191]
  PIN r0_rd_out[0]
    DIRECTION OUTPUT ;
    USE SIGNAL ;
    SHAPE ABUTMENT ;
    PORT
      LAYER met2 ;
      RECT 135.170 0.000 135.310 0.420 ;
    END
  END r0_rd_out[0]
  PIN r0_rd_out[1]
    DIRECTION OUTPUT ;
    USE SIGNAL ;
    SHAPE ABUTMENT ;
    PORT
      LAYER met2 ;
      RECT 136.550 0.000 136.690 0.420 ;
    END
  END r0_rd_out[1]
  PIN r0_rd_out[2]
    DIRECTION OUTPUT ;
    USE SIGNAL ;
    SHAPE ABUTMENT ;
    PORT
      LAYER met2 ;
      RECT 137.930 0.000 138.070 0.420 ;
    END
  END r0_rd_out[2]
  PIN r0_rd_out[3]
    DIRECTION OUTPUT ;
    USE SIGNAL ;
    SHAPE ABUTMENT ;
    PORT
      LAYER met2 ;
      RECT 139.310 0.000 139.450 0.420 ;
    END
  END r0_rd_out[3]
  PIN r0_rd_out[4]
    DIRECTION OUTPUT ;
    USE SIGNAL ;
    SHAPE ABUTMENT ;
    PORT
      LAYER met2 ;
      RECT 140.690 0.000 140.830 0.420 ;
    END
  END r0_rd_out[4]
  PIN r0_rd_out[5]
    DIRECTION OUTPUT ;
    USE SIGNAL ;
    SHAPE ABUTMENT ;
    PORT
      LAYER met2 ;
      RECT 142.070 0.000 142.210 0.420 ;
    END
  END r0_rd_out[5]
  PIN r0_rd_out[6]
    DIRECTION OUTPUT ;
    USE SIGNAL ;
    SHAPE ABUTMENT ;
    PORT
      LAYER met2 ;
      RECT 143.450 0.000 143.590 0.420 ;
    END
  END r0_rd_out[6]
  PIN r0_rd_out[7]
    DIRECTION OUTPUT ;
    USE SIGNAL ;
    SHAPE ABUTMENT ;
    PORT
      LAYER met2 ;
      RECT 144.830 0.000 144.970 0.420 ;
    END
  END r0_rd_out[7]
  PIN r0_rd_out[8]
    DIRECTION OUTPUT ;
    USE SIGNAL ;
    SHAPE ABUTMENT ;
    PORT
      LAYER met2 ;
      RECT 146.210 0.000 146.350 0.420 ;
    END
  END r0_rd_out[8]
  PIN r0_rd_out[9]
    DIRECTION OUTPUT ;
    USE SIGNAL ;
    SHAPE ABUTMENT ;
    PORT
      LAYER met2 ;
      RECT 147.590 0.000 147.730 0.420 ;
    END
  END r0_rd_out[9]
  PIN r0_rd_out[10]
    DIRECTION OUTPUT ;
    USE SIGNAL ;
    SHAPE ABUTMENT ;
    PORT
      LAYER met2 ;
      RECT 148.970 0.000 149.110 0.420 ;
    END
  END r0_rd_out[10]
  PIN r0_rd_out[11]
    DIRECTION OUTPUT ;
    USE SIGNAL ;
    SHAPE ABUTMENT ;
    PORT
      LAYER met2 ;
      RECT 150.350 0.000 150.490 0.420 ;
    END
  END r0_rd_out[11]
  PIN r0_rd_out[12]
    DIRECTION OUTPUT ;
    USE SIGNAL ;
    SHAPE ABUTMENT ;
    PORT
      LAYER met2 ;
      RECT 151.730 0.000 151.870 0.420 ;
    END
  END r0_rd_out[12]
  PIN r0_rd_out[13]
    DIRECTION OUTPUT ;
    USE SIGNAL ;
    SHAPE ABUTMENT ;
    PORT
      LAYER met2 ;
      RECT 153.110 0.000 153.250 0.420 ;
    END
  END r0_rd_out[13]
  PIN r0_rd_out[14]
    DIRECTION OUTPUT ;
    USE SIGNAL ;
    SHAPE ABUTMENT ;
    PORT
      LAYER met2 ;
      RECT 154.490 0.000 154.630 0.420 ;
    END
  END r0_rd_out[14]
  PIN r0_rd_out[15]
    DIRECTION OUTPUT ;
    USE SIGNAL ;
    SHAPE ABUTMENT ;
    PORT
      LAYER met2 ;
      RECT 155.870 0.000 156.010 0.420 ;
    END
  END r0_rd_out[15]
  PIN r0_rd_out[16]
    DIRECTION OUTPUT ;
    USE SIGNAL ;
    SHAPE ABUTMENT ;
    PORT
      LAYER met2 ;
      RECT 157.250 0.000 157.390 0.420 ;
    END
  END r0_rd_out[16]
  PIN r0_rd_out[17]
    DIRECTION OUTPUT ;
    USE SIGNAL ;
    SHAPE ABUTMENT ;
    PORT
      LAYER met2 ;
      RECT 158.630 0.000 158.770 0.420 ;
    END
  END r0_rd_out[17]
  PIN r0_rd_out[18]
    DIRECTION OUTPUT ;
    USE SIGNAL ;
    SHAPE ABUTMENT ;
    PORT
      LAYER met2 ;
      RECT 160.010 0.000 160.150 0.420 ;
    END
  END r0_rd_out[18]
  PIN r0_rd_out[19]
    DIRECTION OUTPUT ;
    USE SIGNAL ;
    SHAPE ABUTMENT ;
    PORT
      LAYER met2 ;
      RECT 161.390 0.000 161.530 0.420 ;
    END
  END r0_rd_out[19]
  PIN r0_rd_out[20]
    DIRECTION OUTPUT ;
    USE SIGNAL ;
    SHAPE ABUTMENT ;
    PORT
      LAYER met2 ;
      RECT 162.770 0.000 162.910 0.420 ;
    END
  END r0_rd_out[20]
  PIN r0_rd_out[21]
    DIRECTION OUTPUT ;
    USE SIGNAL ;
    SHAPE ABUTMENT ;
    PORT
      LAYER met2 ;
      RECT 164.150 0.000 164.290 0.420 ;
    END
  END r0_rd_out[21]
  PIN r0_rd_out[22]
    DIRECTION OUTPUT ;
    USE SIGNAL ;
    SHAPE ABUTMENT ;
    PORT
      LAYER met2 ;
      RECT 165.530 0.000 165.670 0.420 ;
    END
  END r0_rd_out[22]
  PIN r0_rd_out[23]
    DIRECTION OUTPUT ;
    USE SIGNAL ;
    SHAPE ABUTMENT ;
    PORT
      LAYER met2 ;
      RECT 166.910 0.000 167.050 0.420 ;
    END
  END r0_rd_out[23]
  PIN r0_rd_out[24]
    DIRECTION OUTPUT ;
    USE SIGNAL ;
    SHAPE ABUTMENT ;
    PORT
      LAYER met2 ;
      RECT 168.290 0.000 168.430 0.420 ;
    END
  END r0_rd_out[24]
  PIN r0_rd_out[25]
    DIRECTION OUTPUT ;
    USE SIGNAL ;
    SHAPE ABUTMENT ;
    PORT
      LAYER met2 ;
      RECT 169.670 0.000 169.810 0.420 ;
    END
  END r0_rd_out[25]
  PIN r0_rd_out[26]
    DIRECTION OUTPUT ;
    USE SIGNAL ;
    SHAPE ABUTMENT ;
    PORT
      LAYER met2 ;
      RECT 171.050 0.000 171.190 0.420 ;
    END
  END r0_rd_out[26]
  PIN r0_rd_out[27]
    DIRECTION OUTPUT ;
    USE SIGNAL ;
    SHAPE ABUTMENT ;
    PORT
      LAYER met2 ;
      RECT 172.430 0.000 172.570 0.420 ;
    END
  END r0_rd_out[27]
  PIN r0_rd_out[28]
    DIRECTION OUTPUT ;
    USE SIGNAL ;
    SHAPE ABUTMENT ;
    PORT
      LAYER met2 ;
      RECT 173.810 0.000 173.950 0.420 ;
    END
  END r0_rd_out[28]
  PIN r0_rd_out[29]
    DIRECTION OUTPUT ;
    USE SIGNAL ;
    SHAPE ABUTMENT ;
    PORT
      LAYER met2 ;
      RECT 175.190 0.000 175.330 0.420 ;
    END
  END r0_rd_out[29]
  PIN r0_rd_out[30]
    DIRECTION OUTPUT ;
    USE SIGNAL ;
    SHAPE ABUTMENT ;
    PORT
      LAYER met2 ;
      RECT 176.570 0.000 176.710 0.420 ;
    END
  END r0_rd_out[30]
  PIN r0_rd_out[31]
    DIRECTION OUTPUT ;
    USE SIGNAL ;
    SHAPE ABUTMENT ;
    PORT
      LAYER met2 ;
      RECT 177.950 0.000 178.090 0.420 ;
    END
  END r0_rd_out[31]
  PIN r0_rd_out[32]
    DIRECTION OUTPUT ;
    USE SIGNAL ;
    SHAPE ABUTMENT ;
    PORT
      LAYER met2 ;
      RECT 179.330 0.000 179.470 0.420 ;
    END
  END r0_rd_out[32]
  PIN r0_rd_out[33]
    DIRECTION OUTPUT ;
    USE SIGNAL ;
    SHAPE ABUTMENT ;
    PORT
      LAYER met2 ;
      RECT 180.710 0.000 180.850 0.420 ;
    END
  END r0_rd_out[33]
  PIN r0_rd_out[34]
    DIRECTION OUTPUT ;
    USE SIGNAL ;
    SHAPE ABUTMENT ;
    PORT
      LAYER met2 ;
      RECT 182.090 0.000 182.230 0.420 ;
    END
  END r0_rd_out[34]
  PIN r0_rd_out[35]
    DIRECTION OUTPUT ;
    USE SIGNAL ;
    SHAPE ABUTMENT ;
    PORT
      LAYER met2 ;
      RECT 183.470 0.000 183.610 0.420 ;
    END
  END r0_rd_out[35]
  PIN r0_rd_out[36]
    DIRECTION OUTPUT ;
    USE SIGNAL ;
    SHAPE ABUTMENT ;
    PORT
      LAYER met2 ;
      RECT 184.850 0.000 184.990 0.420 ;
    END
  END r0_rd_out[36]
  PIN r0_rd_out[37]
    DIRECTION OUTPUT ;
    USE SIGNAL ;
    SHAPE ABUTMENT ;
    PORT
      LAYER met2 ;
      RECT 186.230 0.000 186.370 0.420 ;
    END
  END r0_rd_out[37]
  PIN r0_rd_out[38]
    DIRECTION OUTPUT ;
    USE SIGNAL ;
    SHAPE ABUTMENT ;
    PORT
      LAYER met2 ;
      RECT 187.610 0.000 187.750 0.420 ;
    END
  END r0_rd_out[38]
  PIN r0_rd_out[39]
    DIRECTION OUTPUT ;
    USE SIGNAL ;
    SHAPE ABUTMENT ;
    PORT
      LAYER met2 ;
      RECT 188.990 0.000 189.130 0.420 ;
    END
  END r0_rd_out[39]
  PIN r0_rd_out[40]
    DIRECTION OUTPUT ;
    USE SIGNAL ;
    SHAPE ABUTMENT ;
    PORT
      LAYER met2 ;
      RECT 190.370 0.000 190.510 0.420 ;
    END
  END r0_rd_out[40]
  PIN r0_rd_out[41]
    DIRECTION OUTPUT ;
    USE SIGNAL ;
    SHAPE ABUTMENT ;
    PORT
      LAYER met2 ;
      RECT 191.750 0.000 191.890 0.420 ;
    END
  END r0_rd_out[41]
  PIN r0_rd_out[42]
    DIRECTION OUTPUT ;
    USE SIGNAL ;
    SHAPE ABUTMENT ;
    PORT
      LAYER met2 ;
      RECT 193.130 0.000 193.270 0.420 ;
    END
  END r0_rd_out[42]
  PIN r0_rd_out[43]
    DIRECTION OUTPUT ;
    USE SIGNAL ;
    SHAPE ABUTMENT ;
    PORT
      LAYER met2 ;
      RECT 194.510 0.000 194.650 0.420 ;
    END
  END r0_rd_out[43]
  PIN r0_rd_out[44]
    DIRECTION OUTPUT ;
    USE SIGNAL ;
    SHAPE ABUTMENT ;
    PORT
      LAYER met2 ;
      RECT 195.890 0.000 196.030 0.420 ;
    END
  END r0_rd_out[44]
  PIN r0_rd_out[45]
    DIRECTION OUTPUT ;
    USE SIGNAL ;
    SHAPE ABUTMENT ;
    PORT
      LAYER met2 ;
      RECT 197.270 0.000 197.410 0.420 ;
    END
  END r0_rd_out[45]
  PIN r0_rd_out[46]
    DIRECTION OUTPUT ;
    USE SIGNAL ;
    SHAPE ABUTMENT ;
    PORT
      LAYER met2 ;
      RECT 198.650 0.000 198.790 0.420 ;
    END
  END r0_rd_out[46]
  PIN r0_rd_out[47]
    DIRECTION OUTPUT ;
    USE SIGNAL ;
    SHAPE ABUTMENT ;
    PORT
      LAYER met2 ;
      RECT 200.030 0.000 200.170 0.420 ;
    END
  END r0_rd_out[47]
  PIN r0_rd_out[48]
    DIRECTION OUTPUT ;
    USE SIGNAL ;
    SHAPE ABUTMENT ;
    PORT
      LAYER met2 ;
      RECT 201.410 0.000 201.550 0.420 ;
    END
  END r0_rd_out[48]
  PIN r0_rd_out[49]
    DIRECTION OUTPUT ;
    USE SIGNAL ;
    SHAPE ABUTMENT ;
    PORT
      LAYER met2 ;
      RECT 202.790 0.000 202.930 0.420 ;
    END
  END r0_rd_out[49]
  PIN r0_rd_out[50]
    DIRECTION OUTPUT ;
    USE SIGNAL ;
    SHAPE ABUTMENT ;
    PORT
      LAYER met2 ;
      RECT 204.170 0.000 204.310 0.420 ;
    END
  END r0_rd_out[50]
  PIN r0_rd_out[51]
    DIRECTION OUTPUT ;
    USE SIGNAL ;
    SHAPE ABUTMENT ;
    PORT
      LAYER met2 ;
      RECT 205.550 0.000 205.690 0.420 ;
    END
  END r0_rd_out[51]
  PIN r0_rd_out[52]
    DIRECTION OUTPUT ;
    USE SIGNAL ;
    SHAPE ABUTMENT ;
    PORT
      LAYER met2 ;
      RECT 206.930 0.000 207.070 0.420 ;
    END
  END r0_rd_out[52]
  PIN r0_rd_out[53]
    DIRECTION OUTPUT ;
    USE SIGNAL ;
    SHAPE ABUTMENT ;
    PORT
      LAYER met2 ;
      RECT 208.310 0.000 208.450 0.420 ;
    END
  END r0_rd_out[53]
  PIN r0_rd_out[54]
    DIRECTION OUTPUT ;
    USE SIGNAL ;
    SHAPE ABUTMENT ;
    PORT
      LAYER met2 ;
      RECT 209.690 0.000 209.830 0.420 ;
    END
  END r0_rd_out[54]
  PIN r0_rd_out[55]
    DIRECTION OUTPUT ;
    USE SIGNAL ;
    SHAPE ABUTMENT ;
    PORT
      LAYER met2 ;
      RECT 211.070 0.000 211.210 0.420 ;
    END
  END r0_rd_out[55]
  PIN r0_rd_out[56]
    DIRECTION OUTPUT ;
    USE SIGNAL ;
    SHAPE ABUTMENT ;
    PORT
      LAYER met2 ;
      RECT 212.450 0.000 212.590 0.420 ;
    END
  END r0_rd_out[56]
  PIN r0_rd_out[57]
    DIRECTION OUTPUT ;
    USE SIGNAL ;
    SHAPE ABUTMENT ;
    PORT
      LAYER met2 ;
      RECT 213.830 0.000 213.970 0.420 ;
    END
  END r0_rd_out[57]
  PIN r0_rd_out[58]
    DIRECTION OUTPUT ;
    USE SIGNAL ;
    SHAPE ABUTMENT ;
    PORT
      LAYER met2 ;
      RECT 215.210 0.000 215.350 0.420 ;
    END
  END r0_rd_out[58]
  PIN r0_rd_out[59]
    DIRECTION OUTPUT ;
    USE SIGNAL ;
    SHAPE ABUTMENT ;
    PORT
      LAYER met2 ;
      RECT 216.590 0.000 216.730 0.420 ;
    END
  END r0_rd_out[59]
  PIN r0_rd_out[60]
    DIRECTION OUTPUT ;
    USE SIGNAL ;
    SHAPE ABUTMENT ;
    PORT
      LAYER met2 ;
      RECT 217.970 0.000 218.110 0.420 ;
    END
  END r0_rd_out[60]
  PIN r0_rd_out[61]
    DIRECTION OUTPUT ;
    USE SIGNAL ;
    SHAPE ABUTMENT ;
    PORT
      LAYER met2 ;
      RECT 219.350 0.000 219.490 0.420 ;
    END
  END r0_rd_out[61]
  PIN r0_rd_out[62]
    DIRECTION OUTPUT ;
    USE SIGNAL ;
    SHAPE ABUTMENT ;
    PORT
      LAYER met2 ;
      RECT 220.730 0.000 220.870 0.420 ;
    END
  END r0_rd_out[62]
  PIN r0_rd_out[63]
    DIRECTION OUTPUT ;
    USE SIGNAL ;
    SHAPE ABUTMENT ;
    PORT
      LAYER met2 ;
      RECT 222.110 0.000 222.250 0.420 ;
    END
  END r0_rd_out[63]
  PIN r0_rd_out[64]
    DIRECTION OUTPUT ;
    USE SIGNAL ;
    SHAPE ABUTMENT ;
    PORT
      LAYER met2 ;
      RECT 223.490 0.000 223.630 0.420 ;
    END
  END r0_rd_out[64]
  PIN r0_rd_out[65]
    DIRECTION OUTPUT ;
    USE SIGNAL ;
    SHAPE ABUTMENT ;
    PORT
      LAYER met2 ;
      RECT 224.870 0.000 225.010 0.420 ;
    END
  END r0_rd_out[65]
  PIN r0_rd_out[66]
    DIRECTION OUTPUT ;
    USE SIGNAL ;
    SHAPE ABUTMENT ;
    PORT
      LAYER met2 ;
      RECT 226.250 0.000 226.390 0.420 ;
    END
  END r0_rd_out[66]
  PIN r0_rd_out[67]
    DIRECTION OUTPUT ;
    USE SIGNAL ;
    SHAPE ABUTMENT ;
    PORT
      LAYER met2 ;
      RECT 227.630 0.000 227.770 0.420 ;
    END
  END r0_rd_out[67]
  PIN r0_rd_out[68]
    DIRECTION OUTPUT ;
    USE SIGNAL ;
    SHAPE ABUTMENT ;
    PORT
      LAYER met2 ;
      RECT 229.010 0.000 229.150 0.420 ;
    END
  END r0_rd_out[68]
  PIN r0_rd_out[69]
    DIRECTION OUTPUT ;
    USE SIGNAL ;
    SHAPE ABUTMENT ;
    PORT
      LAYER met2 ;
      RECT 230.390 0.000 230.530 0.420 ;
    END
  END r0_rd_out[69]
  PIN r0_rd_out[70]
    DIRECTION OUTPUT ;
    USE SIGNAL ;
    SHAPE ABUTMENT ;
    PORT
      LAYER met2 ;
      RECT 231.770 0.000 231.910 0.420 ;
    END
  END r0_rd_out[70]
  PIN r0_rd_out[71]
    DIRECTION OUTPUT ;
    USE SIGNAL ;
    SHAPE ABUTMENT ;
    PORT
      LAYER met2 ;
      RECT 233.150 0.000 233.290 0.420 ;
    END
  END r0_rd_out[71]
  PIN r0_rd_out[72]
    DIRECTION OUTPUT ;
    USE SIGNAL ;
    SHAPE ABUTMENT ;
    PORT
      LAYER met2 ;
      RECT 234.530 0.000 234.670 0.420 ;
    END
  END r0_rd_out[72]
  PIN r0_rd_out[73]
    DIRECTION OUTPUT ;
    USE SIGNAL ;
    SHAPE ABUTMENT ;
    PORT
      LAYER met2 ;
      RECT 235.910 0.000 236.050 0.420 ;
    END
  END r0_rd_out[73]
  PIN r0_rd_out[74]
    DIRECTION OUTPUT ;
    USE SIGNAL ;
    SHAPE ABUTMENT ;
    PORT
      LAYER met2 ;
      RECT 237.290 0.000 237.430 0.420 ;
    END
  END r0_rd_out[74]
  PIN r0_rd_out[75]
    DIRECTION OUTPUT ;
    USE SIGNAL ;
    SHAPE ABUTMENT ;
    PORT
      LAYER met2 ;
      RECT 238.670 0.000 238.810 0.420 ;
    END
  END r0_rd_out[75]
  PIN r0_rd_out[76]
    DIRECTION OUTPUT ;
    USE SIGNAL ;
    SHAPE ABUTMENT ;
    PORT
      LAYER met2 ;
      RECT 240.050 0.000 240.190 0.420 ;
    END
  END r0_rd_out[76]
  PIN r0_rd_out[77]
    DIRECTION OUTPUT ;
    USE SIGNAL ;
    SHAPE ABUTMENT ;
    PORT
      LAYER met2 ;
      RECT 241.430 0.000 241.570 0.420 ;
    END
  END r0_rd_out[77]
  PIN r0_rd_out[78]
    DIRECTION OUTPUT ;
    USE SIGNAL ;
    SHAPE ABUTMENT ;
    PORT
      LAYER met2 ;
      RECT 242.810 0.000 242.950 0.420 ;
    END
  END r0_rd_out[78]
  PIN r0_rd_out[79]
    DIRECTION OUTPUT ;
    USE SIGNAL ;
    SHAPE ABUTMENT ;
    PORT
      LAYER met2 ;
      RECT 244.190 0.000 244.330 0.420 ;
    END
  END r0_rd_out[79]
  PIN r0_rd_out[80]
    DIRECTION OUTPUT ;
    USE SIGNAL ;
    SHAPE ABUTMENT ;
    PORT
      LAYER met2 ;
      RECT 245.570 0.000 245.710 0.420 ;
    END
  END r0_rd_out[80]
  PIN r0_rd_out[81]
    DIRECTION OUTPUT ;
    USE SIGNAL ;
    SHAPE ABUTMENT ;
    PORT
      LAYER met2 ;
      RECT 246.950 0.000 247.090 0.420 ;
    END
  END r0_rd_out[81]
  PIN r0_rd_out[82]
    DIRECTION OUTPUT ;
    USE SIGNAL ;
    SHAPE ABUTMENT ;
    PORT
      LAYER met2 ;
      RECT 248.330 0.000 248.470 0.420 ;
    END
  END r0_rd_out[82]
  PIN r0_rd_out[83]
    DIRECTION OUTPUT ;
    USE SIGNAL ;
    SHAPE ABUTMENT ;
    PORT
      LAYER met2 ;
      RECT 249.710 0.000 249.850 0.420 ;
    END
  END r0_rd_out[83]
  PIN r0_rd_out[84]
    DIRECTION OUTPUT ;
    USE SIGNAL ;
    SHAPE ABUTMENT ;
    PORT
      LAYER met2 ;
      RECT 251.090 0.000 251.230 0.420 ;
    END
  END r0_rd_out[84]
  PIN r0_rd_out[85]
    DIRECTION OUTPUT ;
    USE SIGNAL ;
    SHAPE ABUTMENT ;
    PORT
      LAYER met2 ;
      RECT 252.470 0.000 252.610 0.420 ;
    END
  END r0_rd_out[85]
  PIN r0_rd_out[86]
    DIRECTION OUTPUT ;
    USE SIGNAL ;
    SHAPE ABUTMENT ;
    PORT
      LAYER met2 ;
      RECT 253.850 0.000 253.990 0.420 ;
    END
  END r0_rd_out[86]
  PIN r0_rd_out[87]
    DIRECTION OUTPUT ;
    USE SIGNAL ;
    SHAPE ABUTMENT ;
    PORT
      LAYER met2 ;
      RECT 255.230 0.000 255.370 0.420 ;
    END
  END r0_rd_out[87]
  PIN r0_rd_out[88]
    DIRECTION OUTPUT ;
    USE SIGNAL ;
    SHAPE ABUTMENT ;
    PORT
      LAYER met2 ;
      RECT 256.610 0.000 256.750 0.420 ;
    END
  END r0_rd_out[88]
  PIN r0_rd_out[89]
    DIRECTION OUTPUT ;
    USE SIGNAL ;
    SHAPE ABUTMENT ;
    PORT
      LAYER met2 ;
      RECT 257.990 0.000 258.130 0.420 ;
    END
  END r0_rd_out[89]
  PIN r0_rd_out[90]
    DIRECTION OUTPUT ;
    USE SIGNAL ;
    SHAPE ABUTMENT ;
    PORT
      LAYER met2 ;
      RECT 259.370 0.000 259.510 0.420 ;
    END
  END r0_rd_out[90]
  PIN r0_rd_out[91]
    DIRECTION OUTPUT ;
    USE SIGNAL ;
    SHAPE ABUTMENT ;
    PORT
      LAYER met2 ;
      RECT 260.750 0.000 260.890 0.420 ;
    END
  END r0_rd_out[91]
  PIN r0_rd_out[92]
    DIRECTION OUTPUT ;
    USE SIGNAL ;
    SHAPE ABUTMENT ;
    PORT
      LAYER met2 ;
      RECT 262.130 0.000 262.270 0.420 ;
    END
  END r0_rd_out[92]
  PIN r0_rd_out[93]
    DIRECTION OUTPUT ;
    USE SIGNAL ;
    SHAPE ABUTMENT ;
    PORT
      LAYER met2 ;
      RECT 263.510 0.000 263.650 0.420 ;
    END
  END r0_rd_out[93]
  PIN r0_rd_out[94]
    DIRECTION OUTPUT ;
    USE SIGNAL ;
    SHAPE ABUTMENT ;
    PORT
      LAYER met2 ;
      RECT 264.890 0.000 265.030 0.420 ;
    END
  END r0_rd_out[94]
  PIN r0_rd_out[95]
    DIRECTION OUTPUT ;
    USE SIGNAL ;
    SHAPE ABUTMENT ;
    PORT
      LAYER met2 ;
      RECT 266.270 0.000 266.410 0.420 ;
    END
  END r0_rd_out[95]
  PIN r0_rd_out[96]
    DIRECTION OUTPUT ;
    USE SIGNAL ;
    SHAPE ABUTMENT ;
    PORT
      LAYER met2 ;
      RECT 135.170 584.380 135.310 584.800 ;
    END
  END r0_rd_out[96]
  PIN r0_rd_out[97]
    DIRECTION OUTPUT ;
    USE SIGNAL ;
    SHAPE ABUTMENT ;
    PORT
      LAYER met2 ;
      RECT 136.550 584.380 136.690 584.800 ;
    END
  END r0_rd_out[97]
  PIN r0_rd_out[98]
    DIRECTION OUTPUT ;
    USE SIGNAL ;
    SHAPE ABUTMENT ;
    PORT
      LAYER met2 ;
      RECT 137.930 584.380 138.070 584.800 ;
    END
  END r0_rd_out[98]
  PIN r0_rd_out[99]
    DIRECTION OUTPUT ;
    USE SIGNAL ;
    SHAPE ABUTMENT ;
    PORT
      LAYER met2 ;
      RECT 139.310 584.380 139.450 584.800 ;
    END
  END r0_rd_out[99]
  PIN r0_rd_out[100]
    DIRECTION OUTPUT ;
    USE SIGNAL ;
    SHAPE ABUTMENT ;
    PORT
      LAYER met2 ;
      RECT 140.690 584.380 140.830 584.800 ;
    END
  END r0_rd_out[100]
  PIN r0_rd_out[101]
    DIRECTION OUTPUT ;
    USE SIGNAL ;
    SHAPE ABUTMENT ;
    PORT
      LAYER met2 ;
      RECT 142.070 584.380 142.210 584.800 ;
    END
  END r0_rd_out[101]
  PIN r0_rd_out[102]
    DIRECTION OUTPUT ;
    USE SIGNAL ;
    SHAPE ABUTMENT ;
    PORT
      LAYER met2 ;
      RECT 143.450 584.380 143.590 584.800 ;
    END
  END r0_rd_out[102]
  PIN r0_rd_out[103]
    DIRECTION OUTPUT ;
    USE SIGNAL ;
    SHAPE ABUTMENT ;
    PORT
      LAYER met2 ;
      RECT 144.830 584.380 144.970 584.800 ;
    END
  END r0_rd_out[103]
  PIN r0_rd_out[104]
    DIRECTION OUTPUT ;
    USE SIGNAL ;
    SHAPE ABUTMENT ;
    PORT
      LAYER met2 ;
      RECT 146.210 584.380 146.350 584.800 ;
    END
  END r0_rd_out[104]
  PIN r0_rd_out[105]
    DIRECTION OUTPUT ;
    USE SIGNAL ;
    SHAPE ABUTMENT ;
    PORT
      LAYER met2 ;
      RECT 147.590 584.380 147.730 584.800 ;
    END
  END r0_rd_out[105]
  PIN r0_rd_out[106]
    DIRECTION OUTPUT ;
    USE SIGNAL ;
    SHAPE ABUTMENT ;
    PORT
      LAYER met2 ;
      RECT 148.970 584.380 149.110 584.800 ;
    END
  END r0_rd_out[106]
  PIN r0_rd_out[107]
    DIRECTION OUTPUT ;
    USE SIGNAL ;
    SHAPE ABUTMENT ;
    PORT
      LAYER met2 ;
      RECT 150.350 584.380 150.490 584.800 ;
    END
  END r0_rd_out[107]
  PIN r0_rd_out[108]
    DIRECTION OUTPUT ;
    USE SIGNAL ;
    SHAPE ABUTMENT ;
    PORT
      LAYER met2 ;
      RECT 151.730 584.380 151.870 584.800 ;
    END
  END r0_rd_out[108]
  PIN r0_rd_out[109]
    DIRECTION OUTPUT ;
    USE SIGNAL ;
    SHAPE ABUTMENT ;
    PORT
      LAYER met2 ;
      RECT 153.110 584.380 153.250 584.800 ;
    END
  END r0_rd_out[109]
  PIN r0_rd_out[110]
    DIRECTION OUTPUT ;
    USE SIGNAL ;
    SHAPE ABUTMENT ;
    PORT
      LAYER met2 ;
      RECT 154.490 584.380 154.630 584.800 ;
    END
  END r0_rd_out[110]
  PIN r0_rd_out[111]
    DIRECTION OUTPUT ;
    USE SIGNAL ;
    SHAPE ABUTMENT ;
    PORT
      LAYER met2 ;
      RECT 155.870 584.380 156.010 584.800 ;
    END
  END r0_rd_out[111]
  PIN r0_rd_out[112]
    DIRECTION OUTPUT ;
    USE SIGNAL ;
    SHAPE ABUTMENT ;
    PORT
      LAYER met2 ;
      RECT 157.250 584.380 157.390 584.800 ;
    END
  END r0_rd_out[112]
  PIN r0_rd_out[113]
    DIRECTION OUTPUT ;
    USE SIGNAL ;
    SHAPE ABUTMENT ;
    PORT
      LAYER met2 ;
      RECT 158.630 584.380 158.770 584.800 ;
    END
  END r0_rd_out[113]
  PIN r0_rd_out[114]
    DIRECTION OUTPUT ;
    USE SIGNAL ;
    SHAPE ABUTMENT ;
    PORT
      LAYER met2 ;
      RECT 160.010 584.380 160.150 584.800 ;
    END
  END r0_rd_out[114]
  PIN r0_rd_out[115]
    DIRECTION OUTPUT ;
    USE SIGNAL ;
    SHAPE ABUTMENT ;
    PORT
      LAYER met2 ;
      RECT 161.390 584.380 161.530 584.800 ;
    END
  END r0_rd_out[115]
  PIN r0_rd_out[116]
    DIRECTION OUTPUT ;
    USE SIGNAL ;
    SHAPE ABUTMENT ;
    PORT
      LAYER met2 ;
      RECT 162.770 584.380 162.910 584.800 ;
    END
  END r0_rd_out[116]
  PIN r0_rd_out[117]
    DIRECTION OUTPUT ;
    USE SIGNAL ;
    SHAPE ABUTMENT ;
    PORT
      LAYER met2 ;
      RECT 164.150 584.380 164.290 584.800 ;
    END
  END r0_rd_out[117]
  PIN r0_rd_out[118]
    DIRECTION OUTPUT ;
    USE SIGNAL ;
    SHAPE ABUTMENT ;
    PORT
      LAYER met2 ;
      RECT 165.530 584.380 165.670 584.800 ;
    END
  END r0_rd_out[118]
  PIN r0_rd_out[119]
    DIRECTION OUTPUT ;
    USE SIGNAL ;
    SHAPE ABUTMENT ;
    PORT
      LAYER met2 ;
      RECT 166.910 584.380 167.050 584.800 ;
    END
  END r0_rd_out[119]
  PIN r0_rd_out[120]
    DIRECTION OUTPUT ;
    USE SIGNAL ;
    SHAPE ABUTMENT ;
    PORT
      LAYER met2 ;
      RECT 168.290 584.380 168.430 584.800 ;
    END
  END r0_rd_out[120]
  PIN r0_rd_out[121]
    DIRECTION OUTPUT ;
    USE SIGNAL ;
    SHAPE ABUTMENT ;
    PORT
      LAYER met2 ;
      RECT 169.670 584.380 169.810 584.800 ;
    END
  END r0_rd_out[121]
  PIN r0_rd_out[122]
    DIRECTION OUTPUT ;
    USE SIGNAL ;
    SHAPE ABUTMENT ;
    PORT
      LAYER met2 ;
      RECT 171.050 584.380 171.190 584.800 ;
    END
  END r0_rd_out[122]
  PIN r0_rd_out[123]
    DIRECTION OUTPUT ;
    USE SIGNAL ;
    SHAPE ABUTMENT ;
    PORT
      LAYER met2 ;
      RECT 172.430 584.380 172.570 584.800 ;
    END
  END r0_rd_out[123]
  PIN r0_rd_out[124]
    DIRECTION OUTPUT ;
    USE SIGNAL ;
    SHAPE ABUTMENT ;
    PORT
      LAYER met2 ;
      RECT 173.810 584.380 173.950 584.800 ;
    END
  END r0_rd_out[124]
  PIN r0_rd_out[125]
    DIRECTION OUTPUT ;
    USE SIGNAL ;
    SHAPE ABUTMENT ;
    PORT
      LAYER met2 ;
      RECT 175.190 584.380 175.330 584.800 ;
    END
  END r0_rd_out[125]
  PIN r0_rd_out[126]
    DIRECTION OUTPUT ;
    USE SIGNAL ;
    SHAPE ABUTMENT ;
    PORT
      LAYER met2 ;
      RECT 176.570 584.380 176.710 584.800 ;
    END
  END r0_rd_out[126]
  PIN r0_rd_out[127]
    DIRECTION OUTPUT ;
    USE SIGNAL ;
    SHAPE ABUTMENT ;
    PORT
      LAYER met2 ;
      RECT 177.950 584.380 178.090 584.800 ;
    END
  END r0_rd_out[127]
  PIN r0_rd_out[128]
    DIRECTION OUTPUT ;
    USE SIGNAL ;
    SHAPE ABUTMENT ;
    PORT
      LAYER met2 ;
      RECT 179.330 584.380 179.470 584.800 ;
    END
  END r0_rd_out[128]
  PIN r0_rd_out[129]
    DIRECTION OUTPUT ;
    USE SIGNAL ;
    SHAPE ABUTMENT ;
    PORT
      LAYER met2 ;
      RECT 180.710 584.380 180.850 584.800 ;
    END
  END r0_rd_out[129]
  PIN r0_rd_out[130]
    DIRECTION OUTPUT ;
    USE SIGNAL ;
    SHAPE ABUTMENT ;
    PORT
      LAYER met2 ;
      RECT 182.090 584.380 182.230 584.800 ;
    END
  END r0_rd_out[130]
  PIN r0_rd_out[131]
    DIRECTION OUTPUT ;
    USE SIGNAL ;
    SHAPE ABUTMENT ;
    PORT
      LAYER met2 ;
      RECT 183.470 584.380 183.610 584.800 ;
    END
  END r0_rd_out[131]
  PIN r0_rd_out[132]
    DIRECTION OUTPUT ;
    USE SIGNAL ;
    SHAPE ABUTMENT ;
    PORT
      LAYER met2 ;
      RECT 184.850 584.380 184.990 584.800 ;
    END
  END r0_rd_out[132]
  PIN r0_rd_out[133]
    DIRECTION OUTPUT ;
    USE SIGNAL ;
    SHAPE ABUTMENT ;
    PORT
      LAYER met2 ;
      RECT 186.230 584.380 186.370 584.800 ;
    END
  END r0_rd_out[133]
  PIN r0_rd_out[134]
    DIRECTION OUTPUT ;
    USE SIGNAL ;
    SHAPE ABUTMENT ;
    PORT
      LAYER met2 ;
      RECT 187.610 584.380 187.750 584.800 ;
    END
  END r0_rd_out[134]
  PIN r0_rd_out[135]
    DIRECTION OUTPUT ;
    USE SIGNAL ;
    SHAPE ABUTMENT ;
    PORT
      LAYER met2 ;
      RECT 188.990 584.380 189.130 584.800 ;
    END
  END r0_rd_out[135]
  PIN r0_rd_out[136]
    DIRECTION OUTPUT ;
    USE SIGNAL ;
    SHAPE ABUTMENT ;
    PORT
      LAYER met2 ;
      RECT 190.370 584.380 190.510 584.800 ;
    END
  END r0_rd_out[136]
  PIN r0_rd_out[137]
    DIRECTION OUTPUT ;
    USE SIGNAL ;
    SHAPE ABUTMENT ;
    PORT
      LAYER met2 ;
      RECT 191.750 584.380 191.890 584.800 ;
    END
  END r0_rd_out[137]
  PIN r0_rd_out[138]
    DIRECTION OUTPUT ;
    USE SIGNAL ;
    SHAPE ABUTMENT ;
    PORT
      LAYER met2 ;
      RECT 193.130 584.380 193.270 584.800 ;
    END
  END r0_rd_out[138]
  PIN r0_rd_out[139]
    DIRECTION OUTPUT ;
    USE SIGNAL ;
    SHAPE ABUTMENT ;
    PORT
      LAYER met2 ;
      RECT 194.510 584.380 194.650 584.800 ;
    END
  END r0_rd_out[139]
  PIN r0_rd_out[140]
    DIRECTION OUTPUT ;
    USE SIGNAL ;
    SHAPE ABUTMENT ;
    PORT
      LAYER met2 ;
      RECT 195.890 584.380 196.030 584.800 ;
    END
  END r0_rd_out[140]
  PIN r0_rd_out[141]
    DIRECTION OUTPUT ;
    USE SIGNAL ;
    SHAPE ABUTMENT ;
    PORT
      LAYER met2 ;
      RECT 197.270 584.380 197.410 584.800 ;
    END
  END r0_rd_out[141]
  PIN r0_rd_out[142]
    DIRECTION OUTPUT ;
    USE SIGNAL ;
    SHAPE ABUTMENT ;
    PORT
      LAYER met2 ;
      RECT 198.650 584.380 198.790 584.800 ;
    END
  END r0_rd_out[142]
  PIN r0_rd_out[143]
    DIRECTION OUTPUT ;
    USE SIGNAL ;
    SHAPE ABUTMENT ;
    PORT
      LAYER met2 ;
      RECT 200.030 584.380 200.170 584.800 ;
    END
  END r0_rd_out[143]
  PIN r0_rd_out[144]
    DIRECTION OUTPUT ;
    USE SIGNAL ;
    SHAPE ABUTMENT ;
    PORT
      LAYER met2 ;
      RECT 201.410 584.380 201.550 584.800 ;
    END
  END r0_rd_out[144]
  PIN r0_rd_out[145]
    DIRECTION OUTPUT ;
    USE SIGNAL ;
    SHAPE ABUTMENT ;
    PORT
      LAYER met2 ;
      RECT 202.790 584.380 202.930 584.800 ;
    END
  END r0_rd_out[145]
  PIN r0_rd_out[146]
    DIRECTION OUTPUT ;
    USE SIGNAL ;
    SHAPE ABUTMENT ;
    PORT
      LAYER met2 ;
      RECT 204.170 584.380 204.310 584.800 ;
    END
  END r0_rd_out[146]
  PIN r0_rd_out[147]
    DIRECTION OUTPUT ;
    USE SIGNAL ;
    SHAPE ABUTMENT ;
    PORT
      LAYER met2 ;
      RECT 205.550 584.380 205.690 584.800 ;
    END
  END r0_rd_out[147]
  PIN r0_rd_out[148]
    DIRECTION OUTPUT ;
    USE SIGNAL ;
    SHAPE ABUTMENT ;
    PORT
      LAYER met2 ;
      RECT 206.930 584.380 207.070 584.800 ;
    END
  END r0_rd_out[148]
  PIN r0_rd_out[149]
    DIRECTION OUTPUT ;
    USE SIGNAL ;
    SHAPE ABUTMENT ;
    PORT
      LAYER met2 ;
      RECT 208.310 584.380 208.450 584.800 ;
    END
  END r0_rd_out[149]
  PIN r0_rd_out[150]
    DIRECTION OUTPUT ;
    USE SIGNAL ;
    SHAPE ABUTMENT ;
    PORT
      LAYER met2 ;
      RECT 209.690 584.380 209.830 584.800 ;
    END
  END r0_rd_out[150]
  PIN r0_rd_out[151]
    DIRECTION OUTPUT ;
    USE SIGNAL ;
    SHAPE ABUTMENT ;
    PORT
      LAYER met2 ;
      RECT 211.070 584.380 211.210 584.800 ;
    END
  END r0_rd_out[151]
  PIN r0_rd_out[152]
    DIRECTION OUTPUT ;
    USE SIGNAL ;
    SHAPE ABUTMENT ;
    PORT
      LAYER met2 ;
      RECT 212.450 584.380 212.590 584.800 ;
    END
  END r0_rd_out[152]
  PIN r0_rd_out[153]
    DIRECTION OUTPUT ;
    USE SIGNAL ;
    SHAPE ABUTMENT ;
    PORT
      LAYER met2 ;
      RECT 213.830 584.380 213.970 584.800 ;
    END
  END r0_rd_out[153]
  PIN r0_rd_out[154]
    DIRECTION OUTPUT ;
    USE SIGNAL ;
    SHAPE ABUTMENT ;
    PORT
      LAYER met2 ;
      RECT 215.210 584.380 215.350 584.800 ;
    END
  END r0_rd_out[154]
  PIN r0_rd_out[155]
    DIRECTION OUTPUT ;
    USE SIGNAL ;
    SHAPE ABUTMENT ;
    PORT
      LAYER met2 ;
      RECT 216.590 584.380 216.730 584.800 ;
    END
  END r0_rd_out[155]
  PIN r0_rd_out[156]
    DIRECTION OUTPUT ;
    USE SIGNAL ;
    SHAPE ABUTMENT ;
    PORT
      LAYER met2 ;
      RECT 217.970 584.380 218.110 584.800 ;
    END
  END r0_rd_out[156]
  PIN r0_rd_out[157]
    DIRECTION OUTPUT ;
    USE SIGNAL ;
    SHAPE ABUTMENT ;
    PORT
      LAYER met2 ;
      RECT 219.350 584.380 219.490 584.800 ;
    END
  END r0_rd_out[157]
  PIN r0_rd_out[158]
    DIRECTION OUTPUT ;
    USE SIGNAL ;
    SHAPE ABUTMENT ;
    PORT
      LAYER met2 ;
      RECT 220.730 584.380 220.870 584.800 ;
    END
  END r0_rd_out[158]
  PIN r0_rd_out[159]
    DIRECTION OUTPUT ;
    USE SIGNAL ;
    SHAPE ABUTMENT ;
    PORT
      LAYER met2 ;
      RECT 222.110 584.380 222.250 584.800 ;
    END
  END r0_rd_out[159]
  PIN r0_rd_out[160]
    DIRECTION OUTPUT ;
    USE SIGNAL ;
    SHAPE ABUTMENT ;
    PORT
      LAYER met2 ;
      RECT 223.490 584.380 223.630 584.800 ;
    END
  END r0_rd_out[160]
  PIN r0_rd_out[161]
    DIRECTION OUTPUT ;
    USE SIGNAL ;
    SHAPE ABUTMENT ;
    PORT
      LAYER met2 ;
      RECT 224.870 584.380 225.010 584.800 ;
    END
  END r0_rd_out[161]
  PIN r0_rd_out[162]
    DIRECTION OUTPUT ;
    USE SIGNAL ;
    SHAPE ABUTMENT ;
    PORT
      LAYER met2 ;
      RECT 226.250 584.380 226.390 584.800 ;
    END
  END r0_rd_out[162]
  PIN r0_rd_out[163]
    DIRECTION OUTPUT ;
    USE SIGNAL ;
    SHAPE ABUTMENT ;
    PORT
      LAYER met2 ;
      RECT 227.630 584.380 227.770 584.800 ;
    END
  END r0_rd_out[163]
  PIN r0_rd_out[164]
    DIRECTION OUTPUT ;
    USE SIGNAL ;
    SHAPE ABUTMENT ;
    PORT
      LAYER met2 ;
      RECT 229.010 584.380 229.150 584.800 ;
    END
  END r0_rd_out[164]
  PIN r0_rd_out[165]
    DIRECTION OUTPUT ;
    USE SIGNAL ;
    SHAPE ABUTMENT ;
    PORT
      LAYER met2 ;
      RECT 230.390 584.380 230.530 584.800 ;
    END
  END r0_rd_out[165]
  PIN r0_rd_out[166]
    DIRECTION OUTPUT ;
    USE SIGNAL ;
    SHAPE ABUTMENT ;
    PORT
      LAYER met2 ;
      RECT 231.770 584.380 231.910 584.800 ;
    END
  END r0_rd_out[166]
  PIN r0_rd_out[167]
    DIRECTION OUTPUT ;
    USE SIGNAL ;
    SHAPE ABUTMENT ;
    PORT
      LAYER met2 ;
      RECT 233.150 584.380 233.290 584.800 ;
    END
  END r0_rd_out[167]
  PIN r0_rd_out[168]
    DIRECTION OUTPUT ;
    USE SIGNAL ;
    SHAPE ABUTMENT ;
    PORT
      LAYER met2 ;
      RECT 234.530 584.380 234.670 584.800 ;
    END
  END r0_rd_out[168]
  PIN r0_rd_out[169]
    DIRECTION OUTPUT ;
    USE SIGNAL ;
    SHAPE ABUTMENT ;
    PORT
      LAYER met2 ;
      RECT 235.910 584.380 236.050 584.800 ;
    END
  END r0_rd_out[169]
  PIN r0_rd_out[170]
    DIRECTION OUTPUT ;
    USE SIGNAL ;
    SHAPE ABUTMENT ;
    PORT
      LAYER met2 ;
      RECT 237.290 584.380 237.430 584.800 ;
    END
  END r0_rd_out[170]
  PIN r0_rd_out[171]
    DIRECTION OUTPUT ;
    USE SIGNAL ;
    SHAPE ABUTMENT ;
    PORT
      LAYER met2 ;
      RECT 238.670 584.380 238.810 584.800 ;
    END
  END r0_rd_out[171]
  PIN r0_rd_out[172]
    DIRECTION OUTPUT ;
    USE SIGNAL ;
    SHAPE ABUTMENT ;
    PORT
      LAYER met2 ;
      RECT 240.050 584.380 240.190 584.800 ;
    END
  END r0_rd_out[172]
  PIN r0_rd_out[173]
    DIRECTION OUTPUT ;
    USE SIGNAL ;
    SHAPE ABUTMENT ;
    PORT
      LAYER met2 ;
      RECT 241.430 584.380 241.570 584.800 ;
    END
  END r0_rd_out[173]
  PIN r0_rd_out[174]
    DIRECTION OUTPUT ;
    USE SIGNAL ;
    SHAPE ABUTMENT ;
    PORT
      LAYER met2 ;
      RECT 242.810 584.380 242.950 584.800 ;
    END
  END r0_rd_out[174]
  PIN r0_rd_out[175]
    DIRECTION OUTPUT ;
    USE SIGNAL ;
    SHAPE ABUTMENT ;
    PORT
      LAYER met2 ;
      RECT 244.190 584.380 244.330 584.800 ;
    END
  END r0_rd_out[175]
  PIN r0_rd_out[176]
    DIRECTION OUTPUT ;
    USE SIGNAL ;
    SHAPE ABUTMENT ;
    PORT
      LAYER met2 ;
      RECT 245.570 584.380 245.710 584.800 ;
    END
  END r0_rd_out[176]
  PIN r0_rd_out[177]
    DIRECTION OUTPUT ;
    USE SIGNAL ;
    SHAPE ABUTMENT ;
    PORT
      LAYER met2 ;
      RECT 246.950 584.380 247.090 584.800 ;
    END
  END r0_rd_out[177]
  PIN r0_rd_out[178]
    DIRECTION OUTPUT ;
    USE SIGNAL ;
    SHAPE ABUTMENT ;
    PORT
      LAYER met2 ;
      RECT 248.330 584.380 248.470 584.800 ;
    END
  END r0_rd_out[178]
  PIN r0_rd_out[179]
    DIRECTION OUTPUT ;
    USE SIGNAL ;
    SHAPE ABUTMENT ;
    PORT
      LAYER met2 ;
      RECT 249.710 584.380 249.850 584.800 ;
    END
  END r0_rd_out[179]
  PIN r0_rd_out[180]
    DIRECTION OUTPUT ;
    USE SIGNAL ;
    SHAPE ABUTMENT ;
    PORT
      LAYER met2 ;
      RECT 251.090 584.380 251.230 584.800 ;
    END
  END r0_rd_out[180]
  PIN r0_rd_out[181]
    DIRECTION OUTPUT ;
    USE SIGNAL ;
    SHAPE ABUTMENT ;
    PORT
      LAYER met2 ;
      RECT 252.470 584.380 252.610 584.800 ;
    END
  END r0_rd_out[181]
  PIN r0_rd_out[182]
    DIRECTION OUTPUT ;
    USE SIGNAL ;
    SHAPE ABUTMENT ;
    PORT
      LAYER met2 ;
      RECT 253.850 584.380 253.990 584.800 ;
    END
  END r0_rd_out[182]
  PIN r0_rd_out[183]
    DIRECTION OUTPUT ;
    USE SIGNAL ;
    SHAPE ABUTMENT ;
    PORT
      LAYER met2 ;
      RECT 255.230 584.380 255.370 584.800 ;
    END
  END r0_rd_out[183]
  PIN r0_rd_out[184]
    DIRECTION OUTPUT ;
    USE SIGNAL ;
    SHAPE ABUTMENT ;
    PORT
      LAYER met2 ;
      RECT 256.610 584.380 256.750 584.800 ;
    END
  END r0_rd_out[184]
  PIN r0_rd_out[185]
    DIRECTION OUTPUT ;
    USE SIGNAL ;
    SHAPE ABUTMENT ;
    PORT
      LAYER met2 ;
      RECT 257.990 584.380 258.130 584.800 ;
    END
  END r0_rd_out[185]
  PIN r0_rd_out[186]
    DIRECTION OUTPUT ;
    USE SIGNAL ;
    SHAPE ABUTMENT ;
    PORT
      LAYER met2 ;
      RECT 259.370 584.380 259.510 584.800 ;
    END
  END r0_rd_out[186]
  PIN r0_rd_out[187]
    DIRECTION OUTPUT ;
    USE SIGNAL ;
    SHAPE ABUTMENT ;
    PORT
      LAYER met2 ;
      RECT 260.750 584.380 260.890 584.800 ;
    END
  END r0_rd_out[187]
  PIN r0_rd_out[188]
    DIRECTION OUTPUT ;
    USE SIGNAL ;
    SHAPE ABUTMENT ;
    PORT
      LAYER met2 ;
      RECT 262.130 584.380 262.270 584.800 ;
    END
  END r0_rd_out[188]
  PIN r0_rd_out[189]
    DIRECTION OUTPUT ;
    USE SIGNAL ;
    SHAPE ABUTMENT ;
    PORT
      LAYER met2 ;
      RECT 263.510 584.380 263.650 584.800 ;
    END
  END r0_rd_out[189]
  PIN r0_rd_out[190]
    DIRECTION OUTPUT ;
    USE SIGNAL ;
    SHAPE ABUTMENT ;
    PORT
      LAYER met2 ;
      RECT 264.890 584.380 265.030 584.800 ;
    END
  END r0_rd_out[190]
  PIN r0_rd_out[191]
    DIRECTION OUTPUT ;
    USE SIGNAL ;
    SHAPE ABUTMENT ;
    PORT
      LAYER met2 ;
      RECT 266.270 584.380 266.410 584.800 ;
    END
  END r0_rd_out[191]
  PIN w0_addr_in[0]
    DIRECTION INPUT ;
    USE SIGNAL ;
    SHAPE ABUTMENT ;
    PORT
      LAYER met3 ;
      RECT 0.000 526.170 0.900 526.470 ;
    END
  END w0_addr_in[0]
  PIN w0_addr_in[1]
    DIRECTION INPUT ;
    USE SIGNAL ;
    SHAPE ABUTMENT ;
    PORT
      LAYER met3 ;
      RECT 0.000 531.610 0.900 531.910 ;
    END
  END w0_addr_in[1]
  PIN w0_addr_in[2]
    DIRECTION INPUT ;
    USE SIGNAL ;
    SHAPE ABUTMENT ;
    PORT
      LAYER met3 ;
      RECT 0.000 537.050 0.900 537.350 ;
    END
  END w0_addr_in[2]
  PIN w0_addr_in[3]
    DIRECTION INPUT ;
    USE SIGNAL ;
    SHAPE ABUTMENT ;
    PORT
      LAYER met3 ;
      RECT 341.340 526.170 342.240 526.470 ;
    END
  END w0_addr_in[3]
  PIN r0_addr_in[0]
    DIRECTION INPUT ;
    USE SIGNAL ;
    SHAPE ABUTMENT ;
    PORT
      LAYER met3 ;
      RECT 0.000 542.490 0.900 542.790 ;
    END
  END r0_addr_in[0]
  PIN r0_addr_in[1]
    DIRECTION INPUT ;
    USE SIGNAL ;
    SHAPE ABUTMENT ;
    PORT
      LAYER met3 ;
      RECT 0.000 547.930 0.900 548.230 ;
    END
  END r0_addr_in[1]
  PIN r0_addr_in[2]
    DIRECTION INPUT ;
    USE SIGNAL ;
    SHAPE ABUTMENT ;
    PORT
      LAYER met3 ;
      RECT 0.000 553.370 0.900 553.670 ;
    END
  END r0_addr_in[2]
  PIN r0_addr_in[3]
    DIRECTION INPUT ;
    USE SIGNAL ;
    SHAPE ABUTMENT ;
    PORT
      LAYER met3 ;
      RECT 341.340 537.050 342.240 537.350 ;
    END
  END r0_addr_in[3]
  PIN w0_we_in
    DIRECTION INPUT ;
    USE SIGNAL ;
    SHAPE ABUTMENT ;
    PORT
      LAYER met2 ;
      RECT 267.650 584.380 267.790 584.800 ;
    END
  END w0_we_in
  PIN w0_ce_in
    DIRECTION INPUT ;
    USE SIGNAL ;
    SHAPE ABUTMENT ;
    PORT
      LAYER met2 ;
      RECT 269.030 584.380 269.170 584.800 ;
    END
  END w0_ce_in
  PIN w0_clk
    DIRECTION INPUT ;
    USE SIGNAL ;
    SHAPE ABUTMENT ;
    PORT
      LAYER met2 ;
      RECT 270.410 584.380 270.550 584.800 ;
    END
  END w0_clk
  PIN r0_ce_in
    DIRECTION INPUT ;
    USE SIGNAL ;
    SHAPE ABUTMENT ;
    PORT
      LAYER met2 ;
      RECT 271.790 584.380 271.930 584.800 ;
    END
  END r0_ce_in
  PIN r0_clk
    DIRECTION INPUT ;
    USE SIGNAL ;
    SHAPE ABUTMENT ;
    PORT
      LAYER met2 ;
      RECT 273.170 584.380 273.310 584.800 ;
    END
  END r0_clk
  PIN VSS
    DIRECTION INOUT ;
    USE GROUND ;
    PORT
      LAYER met4 ;
      RECT 2.160 4.080 3.360 580.720 ;
      RECT 13.040 4.080 14.240 580.720 ;
      RECT 23.920 4.080 25.120 580.720 ;
      RECT 34.800 4.080 36.000 580.720 ;
      RECT 45.680 4.080 46.880 580.720 ;
      RECT 56.560 4.080 57.760 580.720 ;
      RECT 67.440 4.080 68.640 580.720 ;
      RECT 78.320 4.080 79.520 580.720 ;
      RECT 89.200 4.080 90.400 580.720 ;
      RECT 100.080 4.080 101.280 580.720 ;
      RECT 110.960 4.080 112.160 580.720 ;
      RECT 121.840 4.080 123.040 580.720 ;
      RECT 132.720 4.080 133.920 580.720 ;
      RECT 143.600 4.080 144.800 580.720 ;
      RECT 154.480 4.080 155.680 580.720 ;
      RECT 165.360 4.080 166.560 580.720 ;
      RECT 176.240 4.080 177.440 580.720 ;
      RECT 187.120 4.080 188.320 580.720 ;
      RECT 198.000 4.080 199.200 580.720 ;
      RECT 208.880 4.080 210.080 580.720 ;
      RECT 219.760 4.080 220.960 580.720 ;
      RECT 230.640 4.080 231.840 580.720 ;
      RECT 241.520 4.080 242.720 580.720 ;
      RECT 252.400 4.080 253.600 580.720 ;
      RECT 263.280 4.080 264.480 580.720 ;
      RECT 274.160 4.080 275.360 580.720 ;
      RECT 285.040 4.080 286.240 580.720 ;
      RECT 295.920 4.080 297.120 580.720 ;
      RECT 306.800 4.080 308.000 580.720 ;
      RECT 317.680 4.080 318.880 580.720 ;
      RECT 328.560 4.080 329.760 580.720 ;
      RECT 339.440 4.080 340.640 580.720 ;
    END
  END VSS
  PIN VDD
    DIRECTION INOUT ;
    USE POWER ;
    PORT
      LAYER met4 ;
      RECT 2.160 4.080 3.360 580.720 ;
      RECT 13.040 4.080 14.240 580.720 ;
      RECT 23.920 4.080 25.120 580.720 ;
      RECT 34.800 4.080 36.000 580.720 ;
      RECT 45.680 4.080 46.880 580.720 ;
      RECT 56.560 4.080 57.760 580.720 ;
      RECT 67.440 4.080 68.640 580.720 ;
      RECT 78.320 4.080 79.520 580.720 ;
      RECT 89.200 4.080 90.400 580.720 ;
      RECT 100.080 4.080 101.280 580.720 ;
      RECT 110.960 4.080 112.160 580.720 ;
      RECT 121.840 4.080 123.040 580.720 ;
      RECT 132.720 4.080 133.920 580.720 ;
      RECT 143.600 4.080 144.800 580.720 ;
      RECT 154.480 4.080 155.680 580.720 ;
      RECT 165.360 4.080 166.560 580.720 ;
      RECT 176.240 4.080 177.440 580.720 ;
      RECT 187.120 4.080 188.320 580.720 ;
      RECT 198.000 4.080 199.200 580.720 ;
      RECT 208.880 4.080 210.080 580.720 ;
      RECT 219.760 4.080 220.960 580.720 ;
      RECT 230.640 4.080 231.840 580.720 ;
      RECT 241.520 4.080 242.720 580.720 ;
      RECT 252.400 4.080 253.600 580.720 ;
      RECT 263.280 4.080 264.480 580.720 ;
      RECT 274.160 4.080 275.360 580.720 ;
      RECT 285.040 4.080 286.240 580.720 ;
      RECT 295.920 4.080 297.120 580.720 ;
      RECT 306.800 4.080 308.000 580.720 ;
      RECT 317.680 4.080 318.880 580.720 ;
      RECT 328.560 4.080 329.760 580.720 ;
      RECT 339.440 4.080 340.640 580.720 ;
    END
  END VDD
  OBS
    LAYER met1 ;
    RECT 0 0 342.240 584.800 ;
    LAYER met2 ;
    RECT 0 0 342.240 584.800 ;
    LAYER met3 ;
    RECT 0 0 342.240 584.800 ;
    LAYER met4 ;
    RECT 0 0 342.240 584.800 ;
  END
END fakeram_192x16_1r1w

END LIBRARY
